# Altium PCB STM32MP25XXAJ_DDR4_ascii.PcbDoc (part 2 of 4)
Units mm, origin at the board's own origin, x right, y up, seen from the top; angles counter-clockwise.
Board outline 172 x 137 mm, 4 copper layers (Top Layer, Signal Layer 1, Signal Layer 2, Bottom Layer), stack 1.614 mm thick; 226 components, 313 nets, 1113 pads, 850 vias.
Unrouted connection lines stored in the file: 13.

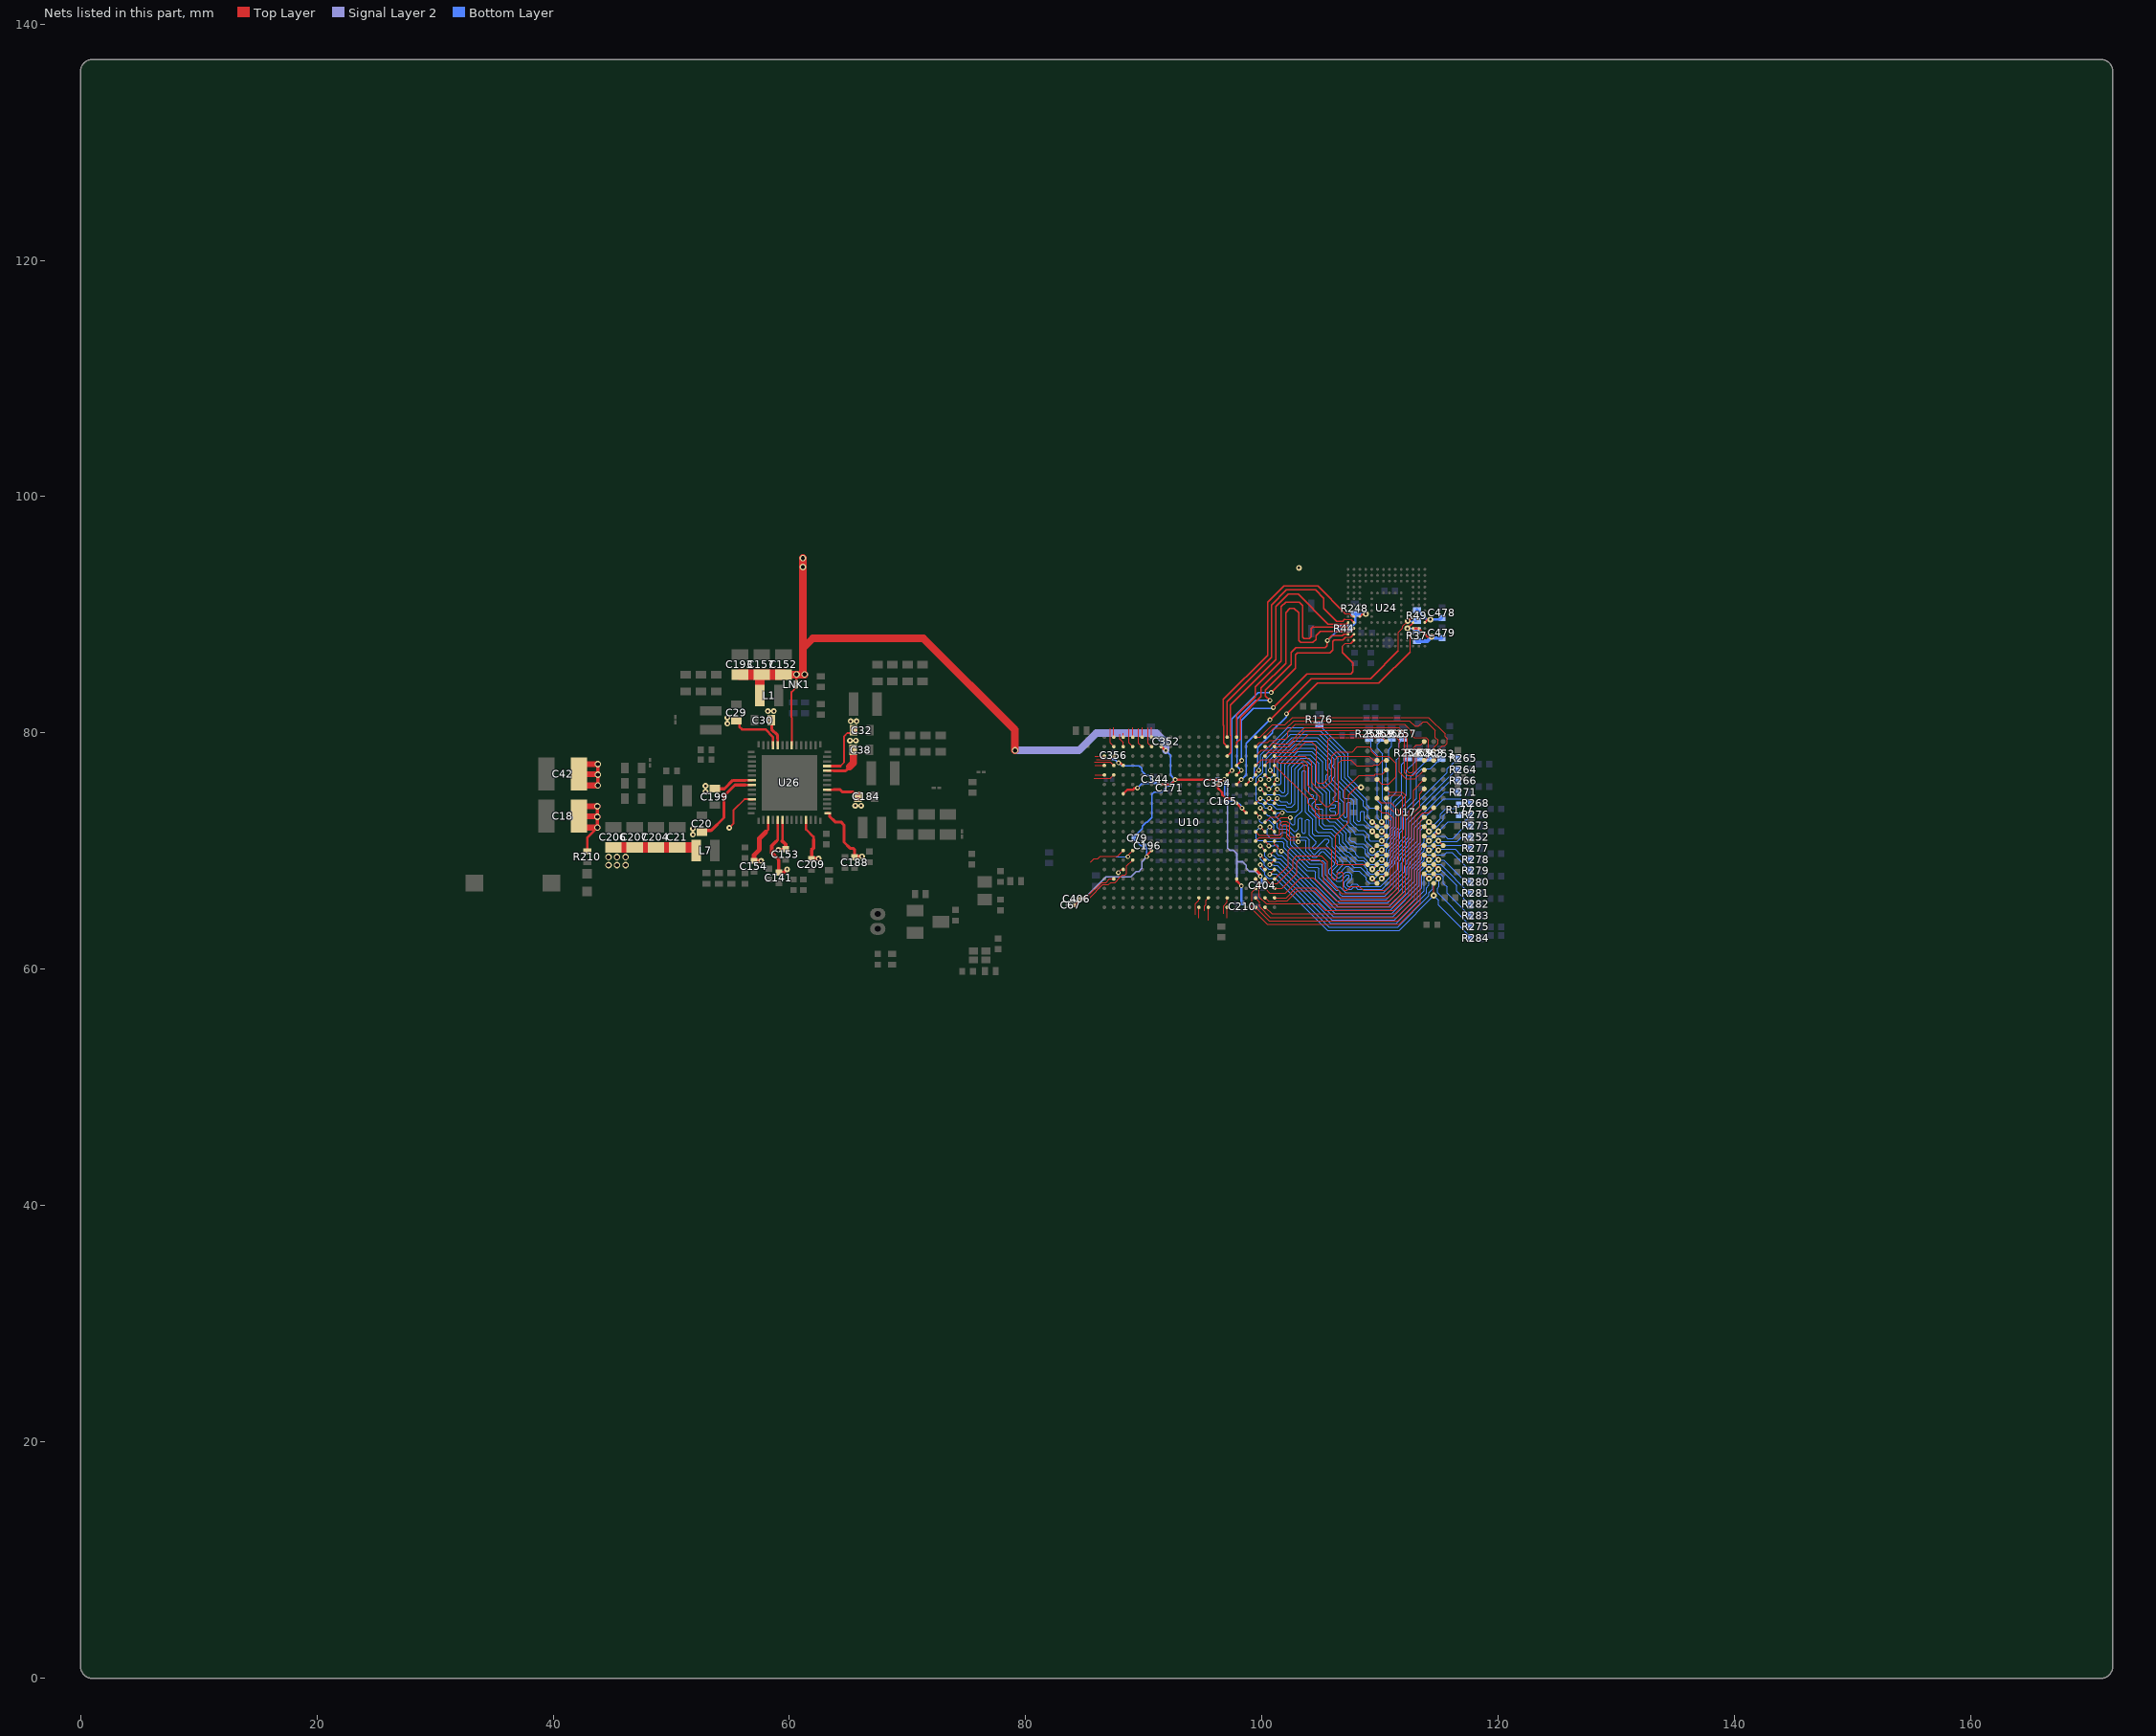
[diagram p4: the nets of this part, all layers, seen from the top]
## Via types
v1: diameter 0.55, hole 0.35, Top Layer to Bottom Layer, 344 vias
v2: diameter 0.5, hole 0.2, Top Layer to Bottom Layer, 250 vias
v3: diameter 0.4, hole 0.2, Top Layer to Bottom Layer, tented both sides, 180 vias
v4: diameter 0.4, hole 0.2, Top Layer to Bottom Layer, 76 vias

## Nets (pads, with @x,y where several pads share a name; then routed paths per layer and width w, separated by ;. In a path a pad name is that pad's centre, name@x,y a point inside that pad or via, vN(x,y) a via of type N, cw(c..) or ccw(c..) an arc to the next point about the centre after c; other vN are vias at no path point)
1V8: C67.2 C79.2 C152.2 C157.2 C165.2 C171.2 C193.2 C196.2 C210.2 C344.2 C352.2 C354.2 C356.2 C404.2 C406.2 C478.2 C479.2 L1.2 LNK1.2 R37.2 R44.2 R49.2 R248.2 U10.B7 U10.D3 U10.F7 U10.F8 U10.F13 U10.G3 U10.H15 U10.J16 U10.N6 U10.R17 U10.T2 U10.T15 U24.C6 U24.M4 U24.N4 U24.P3 U24.P5 | length 130.6
  Top Layer w0.09: v4(84.95,65.985) 84.993,65.985 85.158,66.15 85.228,66.15 86.432,67.355 86.78,67.355 87.075,67.65 U10.T2@87.445,67.65
  Top Layer w0.12: C67.2@84.1,65.4 84.575,65.875 C406.2@84.575,65.975 v4@84.95,65.975 ; v3(90.25,69.525) 90.25,69.65 U10.N6@90.65,70.05
  Top Layer w0.18: U24.C6@108.275,89.85 108.452,90.027 108.727,90.027 v2(108.775,90.075) ; U24.M4@112.775,88.85 U24.N4@113.275,88.85 113.75,88.375 U24.P3@113.775,88.375 ; U24.P3@113.775,88.35 113.975,88.15 v2(114.35,88.15) ; U24.P5@113.775,89.35 114.005,89.58 114.23,89.58 v2(114.25,89.6)
  Top Layer w0.2: LNK1.2@60.6,84.348 v1(60.6,84.95) ; v4(87.85,77.475) 87.888,77.437 88.036,77.437 88.223,77.25 U10.D3@88.25,77.25 ; U10.G3@88.25,74.85 88.612,75.212 89.093,75.212 89.193,75.312 89.412,75.312 v3(89.45,75.35) ; U10.F7@91.45,75.65 92.263,75.65 92.663,76.05 96.526,76.05 96.585,75.99 ; U10.B7@91.45,78.85 91.477,78.85 91.802,78.525 v4(91.85,78.525) ; U10.F13@96.245,75.65 96.585,75.99 ; U10.F13@96.25,75.65 96.25,75.345 96.6,74.995 96.6,74.99 96.638,74.952 96.638,74.749 96.913,74.474 97.426,74.474 U10.J16@98.65,73.25 ; v3(96.8,76.075) 96.762,76.037 96.632,76.037 96.585,75.99 ; U10.T15@97.85,67.65 97.85,67.475 v3(98.25,67.075) ; U10.R17@99.45,68.45 99.812,68.088 99.812,67.913 v3(99.85,67.875)
  Top Layer w0.64: C152.2@59.5,84.95 v1(60.6,84.95) v1(61.28,84.95) 61.142,85.088 61.142,87.175 ; v1(61.142,94.8) 61.142,87.175 ; v1@79.075,78.525 79.075,80.275 71.35,88 61.967,88 61.142,87.175
  Top Layer w0.8: L1.2@57.495,83.175 57.495,84.9 57.545,84.95 C157.2@57.65,84.95
  Top Layer w0.9: C193.2@55.8,84.95 C157.2@57.545,84.95 ; C157.2@57.65,84.95 C152.2@59.5,84.95
  Signal Layer 2 w0.12: v4(84.95,65.985) 86.79,67.825 88.891,67.825 89.341,68.275 89.575,68.275 89.8,68.5 89.8,68.506 89.81,68.516 89.81,69.085 v3(90.25,69.525)
  Signal Layer 2 w0.15: v3(96.8,76.075) 96.825,76.1 96.825,75.999 97.075,75.749 97.075,70.267 97.267,70.075 97.555,70.075 97.875,69.755 97.875,69.425 ; 97.875,69.452 97.875,69.097 ; v3@98.248,67.075 97.875,67.448 97.875,69.097 ; v3(99.85,67.875) 99.425,68.3 98.895,68.3 98.65,68.545 98.65,68.805 98.358,69.097 97.875,69.097
  Signal Layer 2 w0.64: v1@60.6,84.955 v1@61.28,84.955 ; v1(79.1,78.525) 84.507,78.525 85.97,79.988 91.047,79.988 91.85,79.185 v4(91.85,78.525)
  Bottom Layer w0.12: C356.2@87.45,77.85 87.8,77.5 v4@87.825,77.5 ; v4(87.85,77.475) 88.125,77.2 89.258,77.2 89.268,77.21 89.599,77.21 89.81,76.999 89.81,76.781 90.141,76.45 90.384,76.45 ; C79.2@89.15,71.125 89.29,70.985 89.29,70.892 89.566,70.616 89.599,70.616 89.74,70.475 90,70.475 90.226,70.249 90.226,69.549 v3(90.25,69.525) ; C79.2@89.15,71.175 89.29,71.315 89.29,71.365 89.856,71.931 89.856,72.116 90.176,72.435 90.269,72.435 90.69,72.856 90.69,74.815 90.865,74.99 91.508,74.99 92.028,75.51 92.06,75.51 92.175,75.625 v3@92.6,76.05 ; v3(89.45,75.35) 89.815,75.715 90.399,75.715 90.434,75.75 90.615,75.75 90.61,75.755 ; 90.4,76.45 90.384,76.45 ; C344.2@90.975,75.825 90.905,75.755 90.61,75.755 ; C344.2@91,75.739 92.061,75.739 C171.2@92.159,75.641 ; v4@91.825,78.55 91.9,78.625 C352.2@91.9,79 ; v4(91.85,78.525) 92.25,78.125 92.25,76.45 92.6,76.1 v3@92.6,76.05 ; v3(92.65,76.05) v3@92.6,76.05 ; v3@92.65,76.1 v3@92.7,76.1 ; v3@92.671,76.012 v3@92.71,76.05 ; C354.2@96.224,76.051 96.25,76.075 v3(96.8,76.075) 96.84,76.036 96.84,74.43 96.95,74.32 96.95,74.3 97.025,74.225 97.216,74.225 97.726,74.23 97.811,74.23 98.2,73.841 98.2,73.804 98.262,73.742 98.262,73.662 v3@98.25,73.65 ; 90.384,76.45 90.61,76.224 90.61,75.755
  Bottom Layer w0.15: v3(99.85,67.875) 99.95,67.775 C404.2@99.95,67.375
  Bottom Layer w0.2: v3@98.26,67.143 98.266,67.137 C210.2@98.266,65.523 ; R44.2@107.45,88.825 R44.2@107.425,88.85 107.9,89.325 R248.2@107.9,90.075 ; R248.2@107.85,90.075 R248.2@107.9,90.075 ; R248.2@107.9,90.1 R248.2@107.9,90.075 ; v2@108.8,90.075 v2(108.775,90.075) R248.2@107.9,90.075 ; R49.2@113.1,90.45 113.95,89.6 v2(114.25,89.6) 115.075,89.6 C478.2@115.2,89.725
  Bottom Layer w0.3: R37.2@113.125,87.775 113.975,87.775 v2(114.35,88.15) 114.418,88.15 114.543,88.025 C479.2@115.225,88.025
  other v1: 61.131,94.047
  other v2: 103.125,93.975
  other v3: 98.3,73.65
1V8_FB: LNK1.1 U26.35 | length 5.1
  Top Layer w0.15: U26.35@60.2,78.97 60.2,81.311 60.175,81.336 60.175,83.473 LNK1.1@60.6,83.898
3V3: C21.2 C154.2 C204.2 C206.2 C207.2 L7.2 U26.3 U26.53 | length 15.3
  Top Layer w0.15: v2(54.91,71.977) 55.262,72.329 55.262,73.465 56.197,74.4 U26.53@56.83,74.4 ; U26.53@56.62,74.369 56.919,74.369 U26.53@56.95,74.4
  Top Layer w0.21: 57.973,71.598 58.2,71.825 U26.3@58.2,72.63
  Top Layer w0.3: C154.2@56.975,69.175 C154.2@57,69.175 v2@57.585,69.175
  Top Layer w0.4: C154.2@57,69.175 57.014,69.189 57.014,69.685 57.46,70.131 57.46,71.085 57.973,71.598
  Top Layer w0.9: C206.2@45.087,70.323 C21.2@50.5,70.323 51.862,70.323 L7.2@51.887,70.298
  other v1: 44.687,68.823 45.412,68.823 46.137,68.823 44.687,69.498 45.412,69.498 46.137,69.498
  other v2: 57.61,69.175
5V_STLK: C18.1 C20.2 C29.2 C30.2 C32.2 C38.2 C42.1 C153.2 C184.2 C188.2 C199.2 C209.2 R210.1 U26.6 U26.11 U26.15 U26.20 U26.24 U26.25 U26.38 U26.39 U26.49 U26.50 | length 56.5
  Top Layer w0.15: 64.3,77.2 64.625,77.525 64.625,79.731 64.888,79.994 65.319,79.994 C32.2@65.425,80.1
  Top Layer w0.2: R210.1@42.887,69.97 42.887,71.138 v1(43.751,72.002)
  Top Layer w0.21: C29.2@55.525,81.05 55.762,80.813 55.762,80.513 55.975,80.3 57.964,80.3 58.6,79.664 U26.39@58.6,78.97 ; 56.275,75.6 U26.50@56.83,75.6 ; 56.275,76 U26.49@56.83,76 ; U26.38@59,78.97 59,79.525 ; 59.4,70.85 U26.6@59.4,72.63 ; U26.11@61.4,72.63 61.4,71.843 62.04,71.203 62.04,70.975 ; U26.15@63.17,73.2 U26.15@63.245,73.2 U26.15@63.285,73.2 ; U26.20@63.17,75.2 63.725,75.2 ; U26.24@63.17,76.8 63.725,76.8 ; U26.25@63.17,77.2 64.3,77.2
  Top Layer w0.25: C20.2@52.6,71.75 53.375,71.75 54.45,72.825 54.45,74.669 55.381,75.6 56.275,75.6 ; C199.2@53.675,75.275 54.491,75.275 55.216,76 56.275,76 ; C30.2@58.425,81.075 58.494,81.006 58.494,80.308 59,79.802 59,79.525 ; 63.395,73.095 63.395,72.947 63.871,72.472 64.353,72.472 64.625,72.2 64.625,70.759 65.134,70.25 65.379,70.25 65.525,70.104 C188.2@65.525,69.55 ; 63.725,75.2 64.288,75.2 64.463,75.025 65.347,75.025 65.472,74.9 65.55,74.9 65.747,74.703 C184.2@65.747,74.625 ; 63.725,76.8 64.75,76.8 65.075,77.125
  Top Layer w0.3: v1(43.751,72.002) v1(43.751,72.902) v1(43.751,73.802) ; v1(43.776,75.565) v1(43.776,76.465) v1(43.776,77.365) ; v2(59.065,70.11) 59.675,70.11 59.674,70.111 59.674,70.576 59.4,70.85 ; C209.2@61.85,69.38 C209.2@61.875,69.38 ; 62.04,70.975 62.04,70.269 61.875,70.104 C209.2@61.875,69.38 ; v2(62.46,69.38) C209.2@61.875,69.38 ; C188.2@65.525,69.55 v2(66.135,69.55)
  Top Layer w0.5: C18.1@42.187,72.049 42.235,72.002 v1(43.751,72.002) ; C18.1@42.187,72.961 43.679,72.961 43.737,72.902 v1(43.751,72.902) ; C42.1@42.187,75.612 42.235,75.565 v1(43.776,75.565) ; C42.1@42.187,76.523 43.704,76.523 43.762,76.465 v1(43.776,76.465) ; C18.1@42.246,73.802 v1(43.751,73.802) ; C42.1@42.246,77.365 v1(43.776,77.365)
  Top Layer w0.6: 65.075,77.125 65.4,77.45 C38.2@65.4,78.175
  other v2: 51.825,71.4 51.825,71.9 65.575,73.85 66.075,73.85 52.9,75.025 52.9,75.525 65.125,79.35 65.625,79.35 54.75,80.8 65.175,81 65.675,81 54.75,81.3 58.175,81.85 58.675,81.85
5V_VCONN: C141.1 U26.5 | length 5.7
  Top Layer w0.21: 58.877,70.828 59,70.95 U26.5@59,72.63
  Top Layer w0.3: 58.877,70.828 58.51,70.46 58.51,69.865 59.1,69.275 C141.1@59.1,68.2 59.539,68.2 v2(59.8,68.46)
ANA0: U10.V14 | length 1.4
  Top Layer w0.1: 96.75,64.727 96.75,65.374 97.05,65.674 U10.V14@97.05,66.05
ANA1: U10.W14 | length 0.9
  Top Layer w0.1: 97.05,64.356 U10.W14@97.05,65.25
BOOT0: U10.N3 | length 3.2
  Top Layer w0.1: 85.474,69.068 85.784,69.378 86.12,69.378 86.292,69.55 87.233,69.55 87.253,69.57 87.77,69.57 U10.N3@88.25,70.05
BOOT1: U10.N4 | length 1.6
  Top Layer w0.1: v3@88.645,69.65 U10.N4@89.045,70.05
  Bottom Layer w0.1: 87.652,69.525 v3(88.645,69.525)
BOOT2: U10.R3 | length 0.5
  Top Layer w0.09: v4(87.825,68.185) 87.825,68.199 88.052,68.425 88.225,68.425 U10.R3@88.25,68.45
BOOT3: U10.P4 | length 5.3
  Top Layer w0.09: 85.434,66.088 86.511,67.165 87.008,67.165 87.194,67.351 87.568,67.351 87.745,67.528 87.745,67.569 88.164,67.988 88.423,67.988 88.551,68.116 88.551,68.751 U10.P4@89.05,69.25
COMBOPHY_RX1N: U10.W12 | length 1.1
  Top Layer w0.09: 95.45,64.15 U10.W12@95.45,65.25
COMBOPHY_RX1P: U10.V12 | length 1.2
  Top Layer w0.09: 95.15,64.945 95.15,65.372 95.236,65.459 95.236,65.841 U10.V12@95.445,66.05
COMBOPHY_TX1N: U10.W11 | length 0.9
  Top Layer w0.09: 94.645,64.356 94.645,65.245 U10.W11@94.65,65.25
COMBOPHY_TX1P: U10.V11 | length 1.5
  Top Layer w0.09: 94.35,64.63 94.35,65.564 94.632,65.845 94.632,66.032 U10.V11@94.65,66.05
CSI_CKN: U10.C2 | length 1.6
  Top Layer w0.09: 85.967,77.75 87.15,77.75 U10.C2@87.45,78.05
CSI_CKP: U10.C1 | length 0.8
  Top Layer w0.09: 85.875,78.05 U10.C1@86.65,78.05
CSI_D0N: U10.E1 | length 0.8
  Top Layer w0.09: 85.875,76.45 U10.E1@86.65,76.45
CSI_D0P: U10.E2 | length 1.8
  Top Layer w0.09: 85.794,76.15 87.15,76.15 U10.E2@87.45,76.45
CSI_D1N: U10.D2 | length 1.7
  Top Layer w0.09: 85.823,77.545 87.16,77.545 U10.D2@87.45,77.255
CSI_D1P: U10.D1 | length 0.8
  Top Layer w0.09: 85.875,77.25 U10.D1@86.65,77.25
DDR_A0: R265.1 U10.H19 U17.P3 | length 32.7
  Top Layer w0.09: U10.H19@101.046,74.05 101.062,74.066 101.062,74.261 101.251,74.45 v3(101.275,74.45) ; v2@110.132,69.268 U17.P3@110.527,68.873
  Bottom Layer w0.09: v3(101.275,74.45) 101.55,74.175 102.087,74.175 102.234,74.028 102.402,74.028 102.506,74.133 102.506,77.111 103.259,77.864 103.977,77.864 104.539,77.301 104.539,75.396 105.148,74.788 105.148,74.12 105.01,73.982 104.624,73.982 104.539,73.896 104.539,73.67 104.634,73.575 105.06,73.575 105.148,73.487 105.148,72.317 105.291,72.174 106.035,72.174 106.821,71.388 106.821,70.729 107.329,70.221 107.548,70.221 107.922,69.847 107.922,69.734 108.179,69.477 108.564,69.477 109.162,68.879 109.551,68.879 109.867,69.195 110.048,69.195 110.127,69.273 110.182,69.273 110.712,69.803 110.712,70.062 111.368,70.718 111.368,70.843 111.634,71.108 111.634,71.545 111.983,71.894 111.983,72.95 115.675,76.642 115.675,76.97 116.25,77.545 116.39,77.545 116.6,77.755 R265.1@116.6,77.848
  other v2: 110.125,69.275
DDR_A1: R281.1 U10.N18 U17.P7 | length 25.2
  Top Layer w0.09: v3(99.85,70.45) U10.N18@100.25,70.05 ; U17.P7@113.727,68.873 v2@114.127,68.473
  Bottom Layer w0.09: v3(99.85,70.45) 100.243,70.057 100.243,69.556 100.554,69.246 100.966,69.246 101.138,69.073 101.413,69.073 106.026,64.46 111.107,64.46 113.522,66.875 113.522,67.946 114.049,68.473 114.127,68.473 114.348,68.473 114.75,68.875 115.125,68.875 117.575,66.425 R281.1@117.65,66.425
  other v2: 114.125,68.475
DDR_A2: R268.1 U10.K18 U17.R3 | length 34.4
  Top Layer w0.09: U10.K18@100.255,72.45 100.712,72.907 101.275,72.907 101.618,73.25 v3(101.7,73.25) v3@101.704,73.25 ; v2(110.125,67.675) 110.522,68.073 U17.R3@110.527,68.073
  Bottom Layer w0.09: v3@101.704,73.25 v3(101.7,73.25) 101.335,73.25 101.157,73.073 101.157,72.933 101.58,72.511 101.58,72.244 101.667,72.156 102.229,72.156 102.711,71.674 102.876,71.674 103.088,71.886 103.088,72.733 103.177,72.822 103.299,72.822 103.401,72.72 103.401,71.579 103.478,71.502 103.594,71.502 103.695,71.603 103.695,72.586 103.785,72.675 103.893,72.675 103.988,72.581 103.988,71.363 104.563,70.788 104.563,70.672 104.278,70.387 104.278,70.253 104.369,70.162 104.496,70.162 105.348,71.014 105.554,71.014 105.661,70.907 105.661,70.778 105.468,70.585 105.468,70.442 106.843,69.066 106.843,68.843 106.331,68.331 106.331,68.2 106.413,68.118 106.537,68.118 107.122,68.703 107.328,68.703 107.705,68.325 108.223,68.325 108.802,67.747 108.802,67.523 109.045,67.28 109.726,67.28 v2@110.119,67.673 ; v2@110.127,67.673 110.182,67.673 110.732,68.223 110.732,68.429 111.255,68.952 111.255,69.158 111.472,69.375 111.472,69.517 112.474,70.519 112.474,70.663 112.883,71.071 112.883,71.946 115.37,74.434 117.336,74.434 117.415,74.355 117.415,74.26 R268.1@117.625,74.05
DDR_A3: R279.1 U10.M18 U17.N7 | length 24.3
  Top Layer w0.09: U10.M18@100.25,70.85 100.575,70.525 v3(100.575,70.45) ; U17.N7@113.727,69.673 v2(114.125,69.275)
  Bottom Layer w0.09: v3(100.575,70.45) 100.994,70.45 101.075,70.531 101.269,70.531 101.375,70.425 101.375,70.25 101.242,70.117 101.242,69.79 101.378,69.653 101.653,69.653 106.267,65.04 110.866,65.04 113.102,67.275 113.102,68.304 114.071,69.273 114.328,69.273 114.731,69.677 115.402,69.677 115.624,69.899 116.047,69.899 117.303,68.644 117.42,68.644 117.63,68.434 R279.1@117.63,68.355
DDR_A4: R263.1 U10.G19 U17.N3 | length 30.9
  Top Layer w0.09: U10.G19@101.05,74.854 101.057,74.861 101.057,75.066 101.242,75.25 v3(101.275,75.25) ; v2@110.127,70.073 110.127,70.069 U17.N3@110.53,69.667
  Bottom Layer w0.09: v3@101.285,75.25 101.392,75.25 101.692,74.95 101.835,74.95 101.926,75.041 101.926,77.351 103.019,78.444 104.217,78.444 105.119,77.541 105.119,75.637 105.728,75.028 105.728,74.034 105.809,73.952 106.142,73.952 106.231,73.863 106.231,73.725 106.154,73.648 105.809,73.648 105.728,73.567 105.728,73.441 105.815,73.354 106.133,73.354 106.23,73.258 106.23,73.13 106.151,73.051 105.819,73.051 105.728,72.96 105.728,72.848 105.822,72.754 106.275,72.754 107.501,71.528 107.501,71.25 107.401,71.15 107.401,70.969 107.561,70.809 107.781,70.809 107.98,70.61 108.592,70.61 108.935,70.267 108.935,69.914 109.174,69.675 109.485,69.675 109.823,70.013 110.062,70.013 v2(110.125,70.075) ; v2@110.159,70.075 110.919,70.836 110.919,71.009 111.254,71.343 111.254,71.702 111.553,72.002 111.553,73.453 112.595,74.495 112.595,76.343 113.892,77.64 114.015,77.64 R263.1@114.225,77.85
DDR_A5: R282.1 U10.P19 U17.P8 | length 24.1
  Top Layer w0.09: v3@100.645,68.85 100.647,68.85 101.047,69.25 U10.P19@101.055,69.25 ; U17.P8@114.527,68.873 v2@114.927,68.473
  Bottom Layer w0.09: v3@100.66,68.85 100.951,68.85 101.018,68.783 101.293,68.783 105.906,64.17 111.227,64.17 ; 111.227,64.17 113.725,66.668 113.725,67.834 113.966,68.075 114.36,68.075 114.758,68.473 v2@114.925,68.473 ; v2(114.925,68.475) 115.004,68.397 115.178,68.397 116.47,67.104 116.47,66.605 R282.1@117.625,65.45
  other v3: 100.65,68.85
DDR_A6: R264.1 U10.H18 U17.P2 | length 32.4
  Top Layer w0.09: U10.H18@100.255,74.05 100.575,74.37 v3(100.575,74.45) ; v2@109.327,68.473 U17.P2@109.727,68.873
  Bottom Layer w0.09: v3(100.575,74.45) 100.618,74.45 100.783,74.285 100.923,74.285 101.323,73.885 101.967,73.885 102.114,73.738 102.522,73.738 102.796,74.013 102.796,76.991 103.379,77.574 103.857,77.574 104.249,77.181 104.249,75.276 104.652,74.874 104.652,74.419 104.249,74.016 104.249,73.55 104.858,72.941 104.858,72.197 105.17,71.884 105.914,71.884 106.531,71.267 106.531,70.609 107.209,69.931 107.333,69.931 108.07,69.193 108.559,69.193 v2@109.303,68.449 ; v2@109.327,68.473 109.442,68.473 109.847,68.878 110.29,68.878 110.585,69.173 110.585,69.407 110.902,69.724 110.902,69.919 111.646,70.664 111.646,70.784 112.198,71.335 112.198,72.656 116.442,76.9 R264.1@116.654,76.9
  other v2: 109.325,68.475
DDR_A7: R275.1 U10.R19 U17.R8 | length 24.6
  Top Layer w0.09: v3(100.65,68.05) U10.R19@101.05,68.45 ; U17.R8@114.527,68.073 v2(114.925,67.675)
  Bottom Layer w0.09: v3(100.65,68.05) 101.196,68.05 105.656,63.59 111.477,63.59 114.13,66.243 ; 114.125,66.248 114.125,66.475 114.45,66.8 114.45,67.201 v2(114.925,67.675) 114.994,67.606 114.994,67.017 114.84,66.863 114.84,66.493 117.42,63.913 117.42,63.815 R275.1@117.63,63.605
DDR_A8: R266.1 U10.H17 U17.R2 | length 33.8
  Top Layer w0.09: U10.H17@99.455,74.05 v3@99.85,74.445 ; U17.R2@109.727,68.073 v2@110.127,68.473
  Bottom Layer w0.09: v3(99.85,74.45) 99.9,74.4 100.125,74.4 100.53,73.995 100.803,73.995 101.086,73.712 ; 101.085,73.71 101.199,73.595 101.847,73.595 102.095,73.347 102.882,73.347 103.086,73.551 103.086,76.871 103.499,77.284 103.736,77.284 103.959,77.061 103.959,74.909 104.062,74.805 104.25,74.805 104.362,74.693 104.362,74.547 104.263,74.449 104.053,74.449 ; 104.052,74.449 103.959,74.356 103.959,73.429 104.568,72.821 104.568,71.752 104.725,71.594 105.794,71.594 106.241,71.147 106.241,70.489 107.089,69.641 107.213,69.641 107.948,68.905 108.48,68.905 108.914,68.471 108.914,68.321 109.158,68.077 109.493,68.077 109.826,68.41 110.119,68.41 110.794,69.085 110.794,69.291 111.092,69.589 111.092,69.802 111.908,70.618 111.908,70.709 112.434,71.235 112.434,72.438 115.947,75.95 R266.1@116.6,75.95
  other v2: 110.125,68.475
DDR_A9: R283.1 U10.P18 U17.R7 | length 26
  Top Layer w0.09: v3(99.85,69.65) U10.P18@100.25,69.25 ; U17.R7@113.727,68.073 v2@114.127,67.673
  Bottom Layer w0.09: v3(99.85,69.65) 99.85,69.338 100.195,68.993 100.195,68.81 100.543,68.463 101.204,68.463 105.786,63.88 111.355,63.88 113.925,66.448 113.925,66.914 114.129,67.118 v2@114.129,67.671 ; v2(114.125,67.675) 114.366,67.675 114.761,68.07 115.088,68.07 115.35,67.808 115.35,67.275 115.659,66.966 115.659,66.466 117.293,64.832 117.42,64.832 117.6,64.652 R283.1@117.6,64.525
DDR_A10: R254.1 U10.F19 U17.M3 | length 28.6
  Top Layer w0.09: U10.F19@101.046,75.654 101.046,75.88 101.208,76.042 101.208,76.05 v3(101.275,76.05) ; v2@110.127,70.872 U17.M3@110.526,70.473
  Bottom Layer w0.09: v3@101.285,76.05 101.325,76.09 101.325,77.57 102.779,79.024 104.457,79.024 105.813,77.668 105.813,77.505 105.699,77.391 105.699,77.005 105.85,76.854 105.85,76.449 105.699,76.298 105.699,75.877 106.572,75.004 106.572,74.445 106.902,74.115 ; 106.9,74.115 106.9,72.949 106.986,72.863 107.109,72.863 107.192,72.946 ; 107.19,72.946 107.19,74.067 ; 107.192,74.067 107.275,74.15 107.4,74.15 107.48,74.07 107.48,72.369 108.112,71.737 108.607,71.737 109.055,71.289 109.055,70.967 109.149,70.873 110.187,70.873 110.84,71.526 110.84,71.826 111.142,72.128 111.142,74.127 111.815,74.801 111.815,77.34 R254.1@112.325,77.85
  other v2: 110.125,70.875
DDR_A11: R271.1 U10.K19 U17.T2 | length 31.9
  Top Layer w0.09: U10.K19@101.055,72.45 101.079,72.474 101.259,72.474 101.623,72.838 v3@102.388,72.838 ; v2@109.348,67.663 109.727,67.284 U17.T2@109.727,67.273
  Bottom Layer w0.09: v3(102.39,72.84) 102.39,72.405 102.561,72.234 102.705,72.234 102.798,72.327 102.798,72.853 103.376,73.431 103.376,76.75 103.459,76.833 103.59,76.833 103.669,76.754 103.669,73.309 104.278,72.701 104.278,71.484 104.457,71.304 105.674,71.304 105.951,71.027 105.951,70.368 106.969,69.351 107.09,69.351 107.826,68.614 ; 107.827,68.615 108.343,68.615 v2@109.302,67.657 ; v2@109.327,67.673 109.508,67.673 109.911,68.076 110.288,68.076 110.522,68.31 110.522,68.516 111.018,69.012 111.018,69.218 111.282,69.482 111.282,69.666 112.212,70.596 112.212,70.734 112.66,71.183 112.66,72.195 115.465,75 R271.1@116.6,75
  other v2: 109.325,67.675
DDR_A12: R277.1 U10.L18 U17.M7 | length 25.9
  Top Layer w0.09: v3(99.845,72.05) 99.85,72.05 U10.L18@100.25,71.65 ; U17.M7@113.725,70.475 v2(114.125,70.075)
  Bottom Layer w0.09: v3(99.845,72.05) 99.517,71.722 99.517,71.056 99.67,70.902 100.223,70.902 100.304,70.821 101.68,70.821 101.843,70.658 101.843,70.284 103.792,68.335 104.404,68.335 104.513,68.225 104.513,67.613 106.507,65.62 110.626,65.62 112.682,67.676 112.682,68.478 113.522,69.318 113.522,69.535 114.06,70.073 v2(114.125,70.075) 114.307,70.073 114.713,70.479 117.42,70.479 117.63,70.269 R277.1@117.63,70.255
DDR_A13: R284.1 U10.R18 U17.T8 | length 25
  Top Layer w0.09: v3(99.85,68.85) U10.R18@100.25,68.45 ; v2@114.527,66.248 U17.T8@114.527,67.273
  Bottom Layer w0.09: v3@99.86,68.85 99.86,68.567 100.236,68.191 100.236,67.97 100.505,67.702 101.134,67.702 105.536,63.3 111.597,63.3 114.525,66.228 v2@114.525,66.25 ; v2@114.525,66.275 v2@114.525,66.25 ; R284.1@117.65,62.625 117.65,62.717 114.917,65.449 114.917,65.857 v2@114.525,66.25
  other v2: 114.525,66.25
DDR_ACTN: R256.1 U10.E19 U17.L3 | length 27.5
  Top Layer w0.09: v3@100.68,76.85 100.68,76.82 U10.E19@101.05,76.45 ; v2@110.127,71.673 U17.L3@110.527,71.273
  Bottom Layer w0.09: v3(100.69,76.85) 100.699,76.859 100.699,77.764 102.538,79.604 104.697,79.604 106.43,77.871 106.43,75.966 108.06,74.336 108.06,72.613 108.14,72.532 108.266,72.532 108.35,72.616 108.35,73.309 108.422,73.382 108.564,73.382 108.64,73.306 108.64,72.6 ; 108.642,72.6 109.163,72.078 109.536,72.078 109.728,71.887 109.851,71.887 110.064,71.673 v2@110.127,71.673 ; v2(110.125,71.675) 110.152,71.675 110.726,72.249 110.726,75.326 110.625,75.427 110.625,77 110.53,77.095 110.53,77.516 110.71,77.697 110.71,78.61 110.975,78.875 R256.1@110.975,79.475
DDR_BA0: R253.1 U10.G18 U17.N2 | length 32.1
  Top Layer w0.09: v3@99.85,75.268 v3(99.85,75.265) 99.85,75.258 U10.G18@100.25,74.858 ; v2@109.329,69.271 109.727,69.668 U17.N2@109.727,69.673
  Bottom Layer w0.09: v3(99.85,75.265) 100.313,74.802 101.43,74.802 101.572,74.66 101.956,74.66 102.216,74.921 102.216,77.231 103.139,78.154 104.097,78.154 104.829,77.421 104.829,75.517 105.438,74.908 105.438,72.728 105.702,72.464 106.155,72.464 107.111,71.508 107.111,70.849 107.449,70.511 107.669,70.511 107.788,70.392 108.463,70.392 108.74,70.114 108.74,69.758 109.225,69.273 109.422,69.273 109.827,69.678 110.29,69.678 110.522,69.91 110.522,70.17 111.178,70.826 111.178,70.999 111.444,71.265 111.444,71.623 111.77,71.95 111.77,73.16 113.07,74.46 113.07,76.53 113.504,76.964 114.242,76.964 114.869,77.59 114.965,77.59 R253.1@115.175,77.8
  other v2: 109.325,69.275
DDR_BA1: R280.1 U10.N19 U17.N8 | length 23.5
  Top Layer w0.09: v3(100.65,69.65) U10.N19@101.05,70.05 ; U17.N8@114.527,69.673 v2(114.925,69.275) v2@114.897,69.273
  Bottom Layer w0.09: v3(100.65,69.65) 100.661,69.639 100.982,69.639 101.258,69.363 101.533,69.363 106.146,64.75 110.986,64.75 113.332,67.095 113.332,68.244 113.964,68.876 114.34,68.876 114.738,69.273 v2(114.925,69.275) ; v2(114.925,69.275) 114.958,69.242 115.392,69.242 117.234,67.4 R280.1@117.65,67.4
DDR_BG0: R255.1 U10.F18 U17.M2 | length 28.8
  Top Layer w0.09: U10.F18@100.25,75.65 100.25,75.598 100.575,75.273 v3(100.575,75.25) ; v2@109.335,70.081 109.335,70.093 109.715,70.473 U17.M2@109.727,70.473
  Bottom Layer w0.09: v3@100.585,75.25 100.995,75.66 101.546,75.66 101.63,75.744 101.63,77.465 102.899,78.734 104.337,78.734 105.409,77.662 105.409,76.885 105.56,76.734 105.56,76.569 105.409,76.418 105.409,75.757 106.282,74.884 106.282,74.751 106.018,74.487 106.018,74.359 106.135,74.242 106.365,74.242 106.575,74.032 106.575,72.864 106.866,72.573 107.117,72.573 107.19,72.5 107.19,72.249 107.791,71.648 107.791,71.525 107.906,71.41 108.35,71.41 ; 108.35,71.415 108.518,71.415 108.75,71.183 108.75,70.861 109.327,70.285 109.327,70.081 109.724,70.478 110.293,70.478 110.571,70.757 110.571,70.93 111.064,71.422 111.064,71.781 111.346,72.063 111.346,73.871 112.221,74.746 112.221,76.854 112.97,77.604 112.97,77.64 113.18,77.85 R255.1@113.275,77.85
  other v2: 109.33,70.083
DDR_BG1: R252.1 U10.L19 U17.M9 | length 24.9
  Top Layer w0.09: v3@100.65,72.05 U10.L19@101.05,71.65 ; v2(114.925,70.875) U17.M9@115.327,70.473
  Top Layer w0.2: v3(100.645,72.05) v3@100.65,72.05
  Bottom Layer w0.09: v3(100.645,72.05) 100.428,71.834 100.428,71.377 100.695,71.111 101.8,71.111 102.133,70.778 102.133,70.404 103.743,68.793 103.912,68.625 104.705,68.625 104.803,68.526 104.803,67.734 105.043,67.493 106.627,65.91 110.506,65.91 112.472,67.876 112.472,68.565 113.312,69.405 113.312,69.654 113.704,70.047 113.704,70.216 113.96,70.471 114.295,70.471 114.697,70.873 v2(114.925,70.875) ; v2(114.925,70.875) 114.966,70.833 116.511,70.833 116.876,71.199 R252.1@117.625,71.2
DDR_CASN: R278.1 U10.M19 U17.M8 | length 22.6
  Top Layer w0.09: U10.M19@101.05,70.85 101.05,70.575 v3@101.625,70 ; U17.M8@114.527,70.473 v2(114.925,70.075) v2(114.925,70.075)
  Bottom Layer w0.09: v3@101.63,69.999 101.717,69.999 106.387,65.33 110.746,65.33 112.892,67.475 112.892,68.391 113.73,69.229 113.73,69.439 113.971,69.68 114.438,69.68 114.831,70.073 v2(114.925,70.075) ; v2(114.925,70.075) 115.036,70.075 115.149,70.189 116.332,70.189 116.775,69.746 ; 116.775,69.75 117.225,69.3 R278.1@117.625,69.3
  other v3: 101.63,70
DDR_CKE: R259.1 U10.F17 U17.K2 | length 26.8
  Top Layer w0.09: U10.F17@99.45,75.65 99.87,76.07 v3(99.88,76.07) ; v2@109.333,72.463 109.723,72.073 U17.K2@109.727,72.073
  Bottom Layer w0.09: v3(99.88,76.07) 100.345,76.535 100.345,77.82 102.418,79.894 104.817,79.894 106.72,77.991 106.72,76.086 108.568,74.238 108.568,73.813 108.93,73.451 108.93,72.87 v2(109.325,72.475) 109.408,72.475 109.806,72.077 110.285,72.077 110.52,72.312 110.52,74.025 110.2,74.345 110.2,78.242 109.73,78.712 109.73,79.039 110.025,79.334 R259.1@110.025,79.5
DDR_CLK_N: R177.2 U10.L17 U17.K8 | length 30
  Top Layer w0.09: U10.L17@99.447,71.652 99.744,71.355 101.393,71.355 101.484,71.446 ; 101.485,71.448 101.485,72.289 101.721,72.525 102.116,72.525 102.338,72.303 102.338,71.273 102.426,71.186 102.85,71.186 102.978,71.314 v4(103.058,71.314) ; v2(114.125,72.475) U17.K8@114.527,72.073
  Bottom Layer w0.09: v4(103.058,71.314) 103.134,71.314 103.266,71.183 103.758,71.183 103.987,70.954 103.987,70.134 104.376,69.745 104.488,69.745 104.956,70.212 105.288,70.212 106.38,69.12 106.38,68.789 105.923,68.333 105.923,68.197 106.396,67.725 106.554,67.725 107.069,68.24 107.38,68.24 107.46,68.16 107.621,67.999 107.621,67.672 107.216,67.266 107.216,67.113 107.299,67.03 107.476,67.03 107.656,67.21 108.028,67.21 108.208,67.03 110.042,67.03 111.505,68.493 111.505,69.055 111.722,69.271 111.722,69.413 ; 111.725,69.425 113.151,70.851 113.151,71.847 113.493,72.189 113.836,72.189 v2@114.122,72.475 ; v2(114.125,72.475) 114.166,72.475 114.38,72.261 114.614,72.261 115.1,72.747 115.1,73.115 115.584,73.599 116.348,73.599 116.47,73.721 116.47,73.74 116.68,73.95 R177.2@116.775,73.95
DDR_CLK_P: R177.1 U10.M17 U17.K7 | length 30
  Top Layer w0.09: U10.M17@99.45,70.85 99.745,71.145 101.536,71.145 101.735,71.344 ; U10.M17@99.455,70.85 U10.M17@99.457,70.853 ; 101.735,71.344 101.735,72.186 101.825,72.275 102.013,72.275 102.088,72.2 102.088,71.17 102.322,70.936 102.85,70.936 102.999,70.787 v4(103.058,70.787) ; U17.K7@113.727,72.073 v2(114.125,71.675)
  Bottom Layer w0.09: v4(103.058,70.787) 103.12,70.787 103.266,70.933 103.655,70.933 103.737,70.851 103.737,70.031 104.273,69.495 104.592,69.495 105.059,69.962 105.184,69.962 106.13,69.016 106.13,68.893 105.673,68.436 105.673,68.094 106.292,67.475 106.658,67.475 107.173,67.99 107.277,67.99 107.371,67.895 107.371,67.776 106.966,67.37 106.966,67.01 107.195,66.78 107.58,66.78 107.76,66.96 107.925,66.96 108.104,66.78 110.146,66.78 111.755,68.389 111.755,68.951 111.972,69.168 111.972,69.319 ; 111.975,69.322 113.401,70.747 113.401,71.743 113.596,71.939 113.859,71.939 v2@114.123,71.675 ; v2(114.125,71.675) 114.134,71.675 114.47,72.011 114.716,72.011 cw(c114.925,71.675) 114.72,72.013 115.35,72.643 115.35,73.011 115.687,73.349 116.367,73.349 116.455,73.26 116.565,73.26 R177.1@116.775,73.05
DDR_CSN: R273.1 U10.J17 U17.L7 | length 26.9
  Top Layer w0.09: U10.J17@99.45,73.25 99.8,72.9 v3(99.8,72.85) ; U17.L7@113.727,71.273 v2(114.125,70.875)
  Bottom Layer w0.09: v3@99.806,72.844 99.806,72.526 99.931,72.402 100.094,72.402 100.327,72.634 100.565,72.634 101,72.2 101,71.494 101.093,71.401 101.525,71.401 101.7,71.576 101.989,71.576 102.423,71.142 102.423,70.524 104.032,68.915 105.003,68.915 105.093,68.824 105.093,67.854 106.25,66.697 106.458,66.697 106.601,66.554 106.601,66.346 106.747,66.2 110.386,66.2 112.262,68.076 112.262,68.652 112.55,68.94 112.55,69.085 113.102,69.636 113.102,69.747 113.509,70.155 113.509,70.303 114.082,70.875 v2(114.125,70.875) ; v2@114.099,70.873 114.154,70.873 114.554,71.273 115.518,71.273 115.711,71.08 116.129,71.08 117.157,72.109 117.584,72.109 R273.1@117.63,72.155
DDR_DQ0: U10.W18 U17.F7 | length 22.8
  Top Layer w0.09: U10.W18@100.26,65.25 100.822,64.688 111.248,64.688 112.66,66.1 112.66,73.118 113.34,73.798 113.34,74.89 U17.F7@113.725,75.275
DDR_DQ1: U10.W17 U17.H8 | length 23.6
  Top Layer w0.09: U10.W17@99.45,65.25 99.45,65.237 100.579,64.108 111.489,64.108 113.14,65.759 113.14,72.778 113.603,73.242 114.09,73.242 ; 114.096,73.242 U17.H8@114.527,73.673
DDR_DQ2: U10.V17 U17.H7 | length 23.2
  Top Layer w0.09: U10.V17@99.45,66.05 99.45,66.018 99.78,65.688 99.78,65.317 100.699,64.398 111.368,64.398 112.9,65.929 112.9,72.948 113.627,73.675 U17.H7@113.725,73.675 ; U17.H7@113.725,73.673 U17.H7@113.727,73.673
DDR_DQ3: U10.U17 U17.J7 | length 24.8
  Top Layer w0.09: U10.U17@99.455,66.85 99.15,66.545 99.15,65.111 100.443,63.818 111.609,63.818 113.38,65.589 113.38,72.53 U17.J7@113.725,72.875
DDR_DQ4: U10.T19 U17.J3 | length 22.4
  Top Layer w0.09: U10.T19@101.059,67.645 101.101,67.645 102.209,68.753 102.209,70.061 102.441,70.294 105.635,70.294 105.884,70.045 105.884,67.756 106.061,67.58 106.209,67.58 106.343,67.714 106.343,68.063 106.505,68.224 106.74,68.224 106.857,68.107 106.857,66.783 106.962,66.678 107.182,66.678 107.532,67.028 108.222,67.028 108.572,66.678 110.416,66.678 110.87,67.132 110.87,72.513 110.527,72.856 U17.J3@110.527,72.873
DDR_DQ5: U10.T18 U17.H2 | length 22.4
  Top Layer w0.09: U10.T18@100.255,67.65 100.628,67.277 101.302,67.277 102.604,68.579 102.604,69.281 102.917,69.594 105.005,69.594 105.533,69.065 105.533,67.626 106.771,66.388 110.536,66.388 111.11,66.962 111.11,72.778 110.635,73.253 110.147,73.253 U17.H2@109.727,73.673
DDR_DQ6: U10.U19 U17.H3 | length 21.7
  Top Layer w0.09: U10.U19@101.06,66.85 101.707,66.85 102.952,68.095 102.952,69.095 103.144,69.287 104.852,69.287 105.209,68.929 105.209,67.448 106.559,66.098 110.656,66.098 111.35,66.792 111.35,73.125 110.852,73.623 110.577,73.623 U17.H3@110.527,73.673
DDR_DQ7: U10.U18 U17.G2 | length 22.3
  Top Layer w0.09: U10.U18@100.255,66.85 100.655,66.45 101.979,66.45 103.279,67.75 104.344,67.75 106.286,65.808 110.78,65.808 111.59,66.618 ; U17.G2@109.73,74.467 110.08,74.117 110.877,74.117 111.592,73.402 111.592,66.62
DDR_DQ8: U10.C17 U17.D7 | length 18.5
  Top Layer w0.09: U10.C17@99.455,78.05 99.955,78.55 102.555,78.55 103.913,79.908 103.916,79.908 ; 103.916,79.91 111.064,79.91 111.61,79.364 111.61,76.689 112.18,76.118 112.968,76.118 U17.D7@113.725,76.875
DDR_DQ9: U10.A18 U17.B8 | length 17.6
  Top Layer w0.09: U10.A18@100.25,79.65 100.25,79.66 100.997,80.407 102.073,80.407 102.696,81.03 112.48,81.03 112.935,80.575 113.245,80.575 113.631,80.962 113.937,80.962 114.665,80.234 114.665,79.623 114.88,79.408 114.88,79.113 114.534,78.767 114.534,78.485 U17.B8@114.525,78.475
DDR_DQ10: U10.B17 U17.C7 | length 18.3
  Top Layer w0.09: U10.B17@99.45,78.85 99.803,79.203 100.471,79.203 100.623,79.355 101.196,79.355 101.341,79.5 102,79.5 102.175,79.675 102.175,80.077 102.838,80.74 112.043,80.74 112.65,80.133 112.65,79.829 112.858,79.62 113.868,79.62 114.075,79.413 114.075,78.026 U17.C7@113.725,77.675
DDR_DQ11: U10.A17 U17.C8 | length 20.2
  Top Layer w0.09: U10.A17@99.45,79.65 99.824,79.65 100.871,80.697 101.953,80.697 102.576,81.32 114.085,81.32 115.482,79.923 115.482,79.708 115.68,79.51 115.68,79.128 115.455,78.903 115.25,78.903 114.929,78.582 114.929,78.079 U17.C8@114.525,77.675
DDR_DQ12: U10.D19 U17.D3 | length 14.6
  Top Layer w0.09: U10.D19@101.057,77.257 103.862,74.452 103.862,74.05 104.517,73.395 104.517,73.068 104.811,72.775 106.463,72.775 106.994,73.306 106.994,75.222 108.193,76.42 109.495,76.42 109.598,76.523 110.186,76.523 U17.D3@110.53,76.867
DDR_DQ13: U10.D18 U17.C3 | length 18.7
  Top Layer w0.09: U10.D18@100.252,77.248 100.57,77.565 101.325,77.565 101.445,77.445 103.385,77.445 103.602,77.227 103.602,75.266 104.545,74.323 104.545,73.92 104.807,73.658 104.807,73.189 104.931,73.065 106.318,73.065 106.467,73.214 106.467,77.449 106.735,77.717 107.508,77.717 108,77.225 ; 108,77.221 109.379,77.221 109.465,77.306 109.865,77.306 110.212,77.653 110.516,77.653 U17.C3@110.53,77.667
DDR_DQ14: U10.D17 U17.C2 | length 17.3
  Top Layer w0.09: U10.D17@99.452,77.248 99.96,77.755 103.485,77.755 ; 103.485,77.755 103.892,77.347 103.892,75.575 104.892,74.575 104.892,74.253 105.37,73.775 105.65,73.775 106.177,74.302 106.177,77.761 106.444,78.028 108.775,78.028 108.778,78.03 109.072,78.03 109.413,77.689 109.711,77.689 U17.C2@109.725,77.675
DDR_DQ15: U10.C18 U17.A3 | length 17.6
  Top Layer w0.09: U10.C18@100.252,78.048 100.555,78.35 102.765,78.35 103.665,79.25 104.2,79.25 104.592,78.858 104.592,75.903 104.747,75.748 105.233,75.748 105.597,76.111 105.597,79.425 105.792,79.62 110.18,79.62 U17.A3@110.525,79.275
DDR_DQM0: U10.T17 U17.E7 | length 25.7
  Top Layer w0.09: U10.T17@99.455,67.65 99.755,67.35 99.755,66.128 100.338,65.545 104.775,65.545 105.342,64.978 111.124,64.978 112.42,66.274 112.42,73.395 112.812,73.787 112.812,75.163 U17.E7@113.725,76.075
DDR_DQM1: U10.C19 U17.E2 | length 18.8
  Top Layer w0.09: U10.C19@101.05,78.05 103.616,78.05 104.182,77.484 104.182,75.818 104.621,75.379 105.328,75.379 105.887,75.938 105.887,78.029 106.258,78.4 107.625,78.4 108.055,78.83 109.072,78.83 109.28,78.622 109.28,78.432 109.306,78.406 109.675,78.037 110.721,78.037 111.32,77.439 111.32,76.287 110.707,75.675 110.132,75.675 U17.E2@109.734,76.073
DDR_DQS0_N: U10.V18 U17.F3 | length 23.6
  Top Layer w0.09: U10.V18@100.255,66.05 100.554,65.751 101.164,65.751 101.218,65.805 102.148,65.805 102.986,66.643 104.418,66.643 105.792,65.268 111.004,65.268 112.13,66.395 112.13,74.733 111.873,74.99 110.806,74.99 U17.F3@110.53,75.267
DDR_DQS0_P: U10.V19 U17.G3 | length 21.8
  Top Layer w0.09: U10.V19@101.05,66.05 102.039,66.05 102.883,66.893 104.521,66.893 105.896,65.518 110.9,65.518 111.88,66.498 111.88,74.63 111.769,74.74 110.794,74.74 U17.G3@110.527,74.473
DDR_DQS1_N: U10.B18 U17.A7 | length 19.7
  Top Layer w0.09: U10.B18@100.25,78.85 100.624,78.85 100.919,79.145 101.172,79.145 101.217,79.1 102.241,79.1 103.591,80.45 111.569,80.45 112.291,79.729 112.291,76.771 112.404,76.658 112.691,76.658 112.81,76.777 112.81,78.74 113.053,78.983 113.446,78.983 U17.A7@113.73,79.267
DDR_DQS1_P: U10.B19 U17.B7 | length 18.8
  Top Layer w0.09: U10.B19@101.05,78.85 102.344,78.85 103.694,80.2 103.7,80.2 111.466,80.2 112.041,79.625 112.041,76.667 112.3,76.408 112.794,76.408 113.06,76.674 113.06,78.637 113.156,78.733 113.45,78.733 U17.B7@113.728,78.455
DDR_ODT: R258.1 U10.J19 U17.K3 | length 29.9
  Top Layer w0.09: v3(100.65,73.65) U10.J19@101.05,73.25 ; v2@110.125,72.471 U17.K3@110.53,72.067
  Bottom Layer w0.09: v3@100.655,73.645 100.265,73.645 100.195,73.715 100.195,73.819 99.96,74.053 99.74,74.053 99.492,74.302 99.492,76.17 99.827,76.505 99.853,76.505 100.055,76.707 100.055,77.94 102.298,80.184 104.938,80.184 107.01,78.111 107.01,76.206 108.858,74.358 108.858,73.933 109.121,73.67 109.559,73.67 109.747,73.482 109.747,72.823 v2@110.06,72.51 ; R258.1@109.024,79.5 109.234,79.29 109.234,78.65 109.755,78.129 109.755,74.268 110.125,73.898 v2(110.125,72.475)
DDR_RASN: R276.1 U10.J18 U17.L8 | length 26.4
  Top Layer w0.09: v3(99.85,73.65) U10.J18@100.25,73.25 ; U17.L8@114.527,71.273 v2(114.925,71.675)
  Bottom Layer w0.09: v3(99.85,73.65) 100.483,73.017 100.593,73.017 101.29,72.32 101.29,71.977 101.4,71.866 102.109,71.866 102.713,71.262 102.713,70.644 104.153,69.205 105.123,69.205 105.383,68.944 105.383,67.974 106.369,66.988 106.577,66.988 107.075,66.49 110.266,66.49 112.052,68.276 112.052,68.739 112.262,68.949 112.262,69.198 113.296,70.233 113.296,70.359 113.73,70.792 113.73,70.899 ; 113.73,70.9 113.732,70.919 113.732,71.055 113.95,71.273 114.285,71.273 114.685,71.673 v2(114.925,71.675) ; v2@114.925,71.684 115.734,72.493 117.113,72.493 117.63,73.01 R276.1@117.63,73.105
DDR_RESETN: R176.2 U10.E17 U17.P1 | length 24.9
  Top Layer w0.09: U10.E17@99.449,76.451 99.449,76.686 v3@99.553,76.791 ; v2(108.375,75.4) 107.972,75.4 107.322,74.75 107.322,72.449 106.217,71.344 106.217,69.001 106.343,68.874 U17.P1@108.925,68.874
  Bottom Layer w0.09: v3@99.7,76.85 99.733,76.883 99.733,77.131 99.865,77.263 99.865,78.16 102.178,80.474 104.492,80.474 104.509,80.49 104.64,80.49 R176.2@104.85,80.7 ; R176.2@104.85,80.681 107.3,78.231 107.3,76.338 108.263,75.375 v2@108.374,75.375
  other v3: 99.71,76.85
DDR_WEN: R257.1 U10.E18 U17.L2 | length 27.7
  Top Layer w0.09: U10.E18@100.25,76.45 100.575,76.125 v3(100.575,76.05) ; v2@109.327,71.669 U17.L2@109.73,71.267
  Bottom Layer w0.09: v3@100.578,76.05 101.035,76.507 101.035,77.69 102.659,79.314 104.577,79.314 106.103,77.788 106.103,77.385 105.989,77.271 105.989,77.125 106.14,76.974 106.14,76.329 105.989,76.178 105.989,75.997 106.862,75.124 106.862,74.565 106.976,74.451 107.535,74.451 107.77,74.216 107.77,72.489 107.773,72.489 108.02,72.242 108.556,72.242 108.81,71.988 ; 108.81,71.986 108.987,71.986 109.299,71.673 109.327,71.673 109.728,71.272 110.282,71.272 110.567,71.557 110.567,71.822 110.93,72.185 110.93,74.53 111.383,74.983 111.383,77.733 111.575,77.925 111.575,79.125 R257.1@111.925,79.475
  other v2: 109.325,71.675
DSI_CKN: U10.B4 | length 1.6
  Top Layer w0.09: 88.752,80.357 88.752,79.148 U10.B4@89.05,78.85
DSI_CKP: U10.A4 | length 0.8
  Top Layer w0.09: U10.A4@89.05,79.65 89.05,80.464
DSI_D0N: U10.A6 | length 0.8
  Top Layer w0.1: U10.A6@90.65,79.65 90.65,80.443
DSI_D0P: U10.B6 | length 1.7
  Top Layer w0.1: 90.358,80.404 90.358,79.782 90.35,79.774 90.35,79.526 90.358,79.518 90.358,79.142 U10.B6@90.65,78.85
DSI_D1N: U10.A5 | length 0.8
  Top Layer w0.09: U10.A5@89.85,79.65 89.85,80.464
DSI_D1P: U10.B5 | length 1.7
  Top Layer w0.09: 89.562,80.387 89.562,79.779 89.555,79.772 89.555,79.528 89.562,79.521 89.562,79.138 U10.B5@89.85,78.85
DSI_D2N: U10.A3 | length 0.3
  Top Layer w0.09: U10.A3@88.25,79.65 88.25,79.978
DSI_D2P: U10.B3 | length 1.2
  Top Layer w0.09: 87.951,79.877 87.951,79.502 88.25,79.203 U10.B3@88.25,78.85
DSI_D3N: U10.A2 | length 0.8
  Top Layer w0.09: U10.A2@87.45,79.65 87.45,80.464
DSI_D3P: U10.B2 | length 1.7
  Top Layer w0.09: 87.145,80.38 87.145,79.155 U10.B2@87.45,78.85
eMMC.SDMMC2_CK: R49.1 U10.F15 U24.M6 | length 24.8
  Top Layer w0.09: 111.525,86.961 111.525,88.454 111.525,88.502 111.823,88.8 111.825,88.8 111.905,88.88 111.905,89.03 112.325,89.45 v2(112.325,89.475)
  Top Layer w0.11: U10.F15@97.85,75.65 97.85,75.655 v3(98.245,76.05) ; v4(100.675,81.125) 104.15,84.6 109.164,84.6 111.525,86.961 ; v2@112.4,89.475 v2(112.325,89.475) v2@112.4,89.475 ; v2@112.4,89.475 U24.M6@112.775,89.85 v2@112.4,89.475
  Bottom Layer w0.11: v3(98.245,76.05) 98.643,76.449 98.643,79.114 v4@100.675,81.146 ; v2@112.35,89.45 113.05,89.45 R49.1@113.1,89.5
eMMC.SDMMC2_CMD: R37.1 U10.F16 U24.M5 | length 23.7
  Top Layer w0.09: v2(112.3,88.85) 112.3,88.83 112.525,88.605 112.525,86.875
  Top Layer w0.11: U10.F16@98.645,75.65 v3@99.045,76.05 ; v4@102.077,81.623 104.678,84.225 109.875,84.225 112.525,86.875 ; v2(112.3,88.85) 112.3,88.863 112.775,89.338 U24.M5@112.775,89.35
  Bottom Layer w0.11: v3(99.05,76.05) 99.083,76.05 99.355,76.322 99.355,77.04 99.64,77.325 99.64,78.747 100.89,79.996 100.89,80.198 102.048,81.356 102.048,81.598 v4(102.075,81.625) ; v2@112.286,88.836 v2(112.3,88.85) 112.925,88.85 R37.1@113.125,88.65
eMMC.SDMMC2_D0: R44.1 U10.E15 U24.A3 | length 20.8
  Top Layer w0.11: U10.E15@97.85,76.45 v3(98.25,76.85) ; v4(100.675,82.75) 100.275,83.15 100.275,83.6 102.475,85.8 102.475,86.828 102.864,87.217 105.323,87.217 105.507,87.401 105.507,87.807 v4(105.525,87.825) ; v4@105.508,87.833 105.904,88.229 106.797,88.229 106.918,88.35 U24.A3@107.275,88.35
  Bottom Layer w0.11: v3@98.225,76.85 97.884,77.191 97.884,81.18 99.479,82.775 v4@100.65,82.775 ; v4(105.525,87.825) 106.55,88.85 R44.1@106.55,88.9
eMMC.SDMMC2_D1: U10.A15 U24.A4 | length 22.1
  Top Layer w0.11: U10.A15@97.85,79.65 97.85,81.494 99.427,83.071 99.427,83.896 101.62,86.089 101.62,90.695 101.997,91.073 103.155,91.073 103.425,90.803 103.425,88.125 103.55,88 104,88 104.15,88.15 104.15,88.85 104.284,88.984 107.141,88.984 U24.A4@107.275,88.85
eMMC.SDMMC2_D2: U10.C14 U24.A5 | length 22
  Top Layer w0.11: U10.C14@97.05,78.05 97.355,78.355 97.355,79.776 97.327,79.804 97.327,82.377 101.172,86.222 101.172,90.705 102.209,91.741 103.049,91.741 105.583,89.207 107.126,89.207 U24.A5@107.269,89.35
eMMC.SDMMC2_D3: U10.D15 U24.B2 | length 18.7
  Top Layer w0.09: 106.798,87.348 107.05,87.6 107.525,87.6
  Top Layer w0.11: U10.D15@97.85,77.25 v4(98.275,77.675) ; v4(100.95,82.15) 103.804,85.004 107.523,85.004 107.699,85.18 107.699,85.929 106.798,86.831 106.798,87.348 ; 107.525,87.6 U24.B2@107.775,87.85
  Bottom Layer w0.11: v4@98.25,77.675 98.25,81.068 99.249,82.067 v4@100.847,82.067
eMMC.SDMMC2_D4: U10.E14 U24.B3 | length 19.4
  Top Layer w0.09: 107.095,88.1 107.525,88.1
  Top Layer w0.11: U10.E14@97.05,76.45 v4@97.515,76.915 ; v4(100.775,83.425) 102.825,85.475 102.825,86.6 103.006,86.781 105.745,86.781 106,87.036 106,87.75 106.104,87.853 106.848,87.853 107.095,88.1 ; 107.525,88.1 U24.B3@107.775,88.35
  Bottom Layer w0.11: v4@97.425,76.825 97.425,81.2 99.65,83.425 100.75,83.425 v4(100.775,83.425)
  other v4: 97.45,76.825
eMMC.SDMMC2_D5: U10.B15 U24.B4 | length 22.2
  Top Layer w0.09: 106.8,88.6 107.525,88.6
  Top Layer w0.11: U10.B15@97.85,78.85 97.85,79.2 98.155,79.505 98.155,81.315 99.925,83.085 99.925,83.825 102,85.9 102,90.187 102.359,90.546 102.714,90.546 103.09,90.17 103.09,87.844 103.284,87.65 104.3,87.65 104.575,87.925 104.575,88.225 104.948,88.598 106.798,88.598 ; 107.525,88.6 U24.B4@107.775,88.85
eMMC.SDMMC2_D6: U10.A14 U24.B5 | length 22
  Top Layer w0.09: 107.05,89.6 107.525,89.6
  Top Layer w0.11: U10.A14@97.05,79.65 97.05,80.194 ; 97.05,80.2 97.05,82.65 100.8,86.4 100.8,90.842 102.065,92.107 104.526,92.107 105.225,91.408 105.225,90.534 106.314,89.445 106.818,89.445 106.973,89.6 107.05,89.6 ; 107.525,89.6 U24.B5@107.775,89.35
eMMC.SDMMC2_D7: U10.B14 U24.B6 | length 22.9
  Top Layer w0.09: 107.05,90.1 107.382,90.1 107.617,89.865
  Top Layer w0.11: U10.B14@97.05,78.85 96.745,79.155 96.745,80.613 96.704,80.654 96.704,82.829 100.458,86.583 100.458,91.052 101.835,92.43 104.718,92.43 107.048,90.1 ; 107.617,89.865 107.76,89.865 U24.B6@107.775,89.85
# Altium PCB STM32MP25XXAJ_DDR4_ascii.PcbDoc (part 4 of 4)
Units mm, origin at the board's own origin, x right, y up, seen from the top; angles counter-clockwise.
Board outline 172 x 137 mm, 4 copper layers (Top Layer, Signal Layer 1, Signal Layer 2, Bottom Layer), stack 1.614 mm thick; 226 components, 313 nets, 1113 pads, 850 vias.
Unrouted connection lines stored in the file: 13.

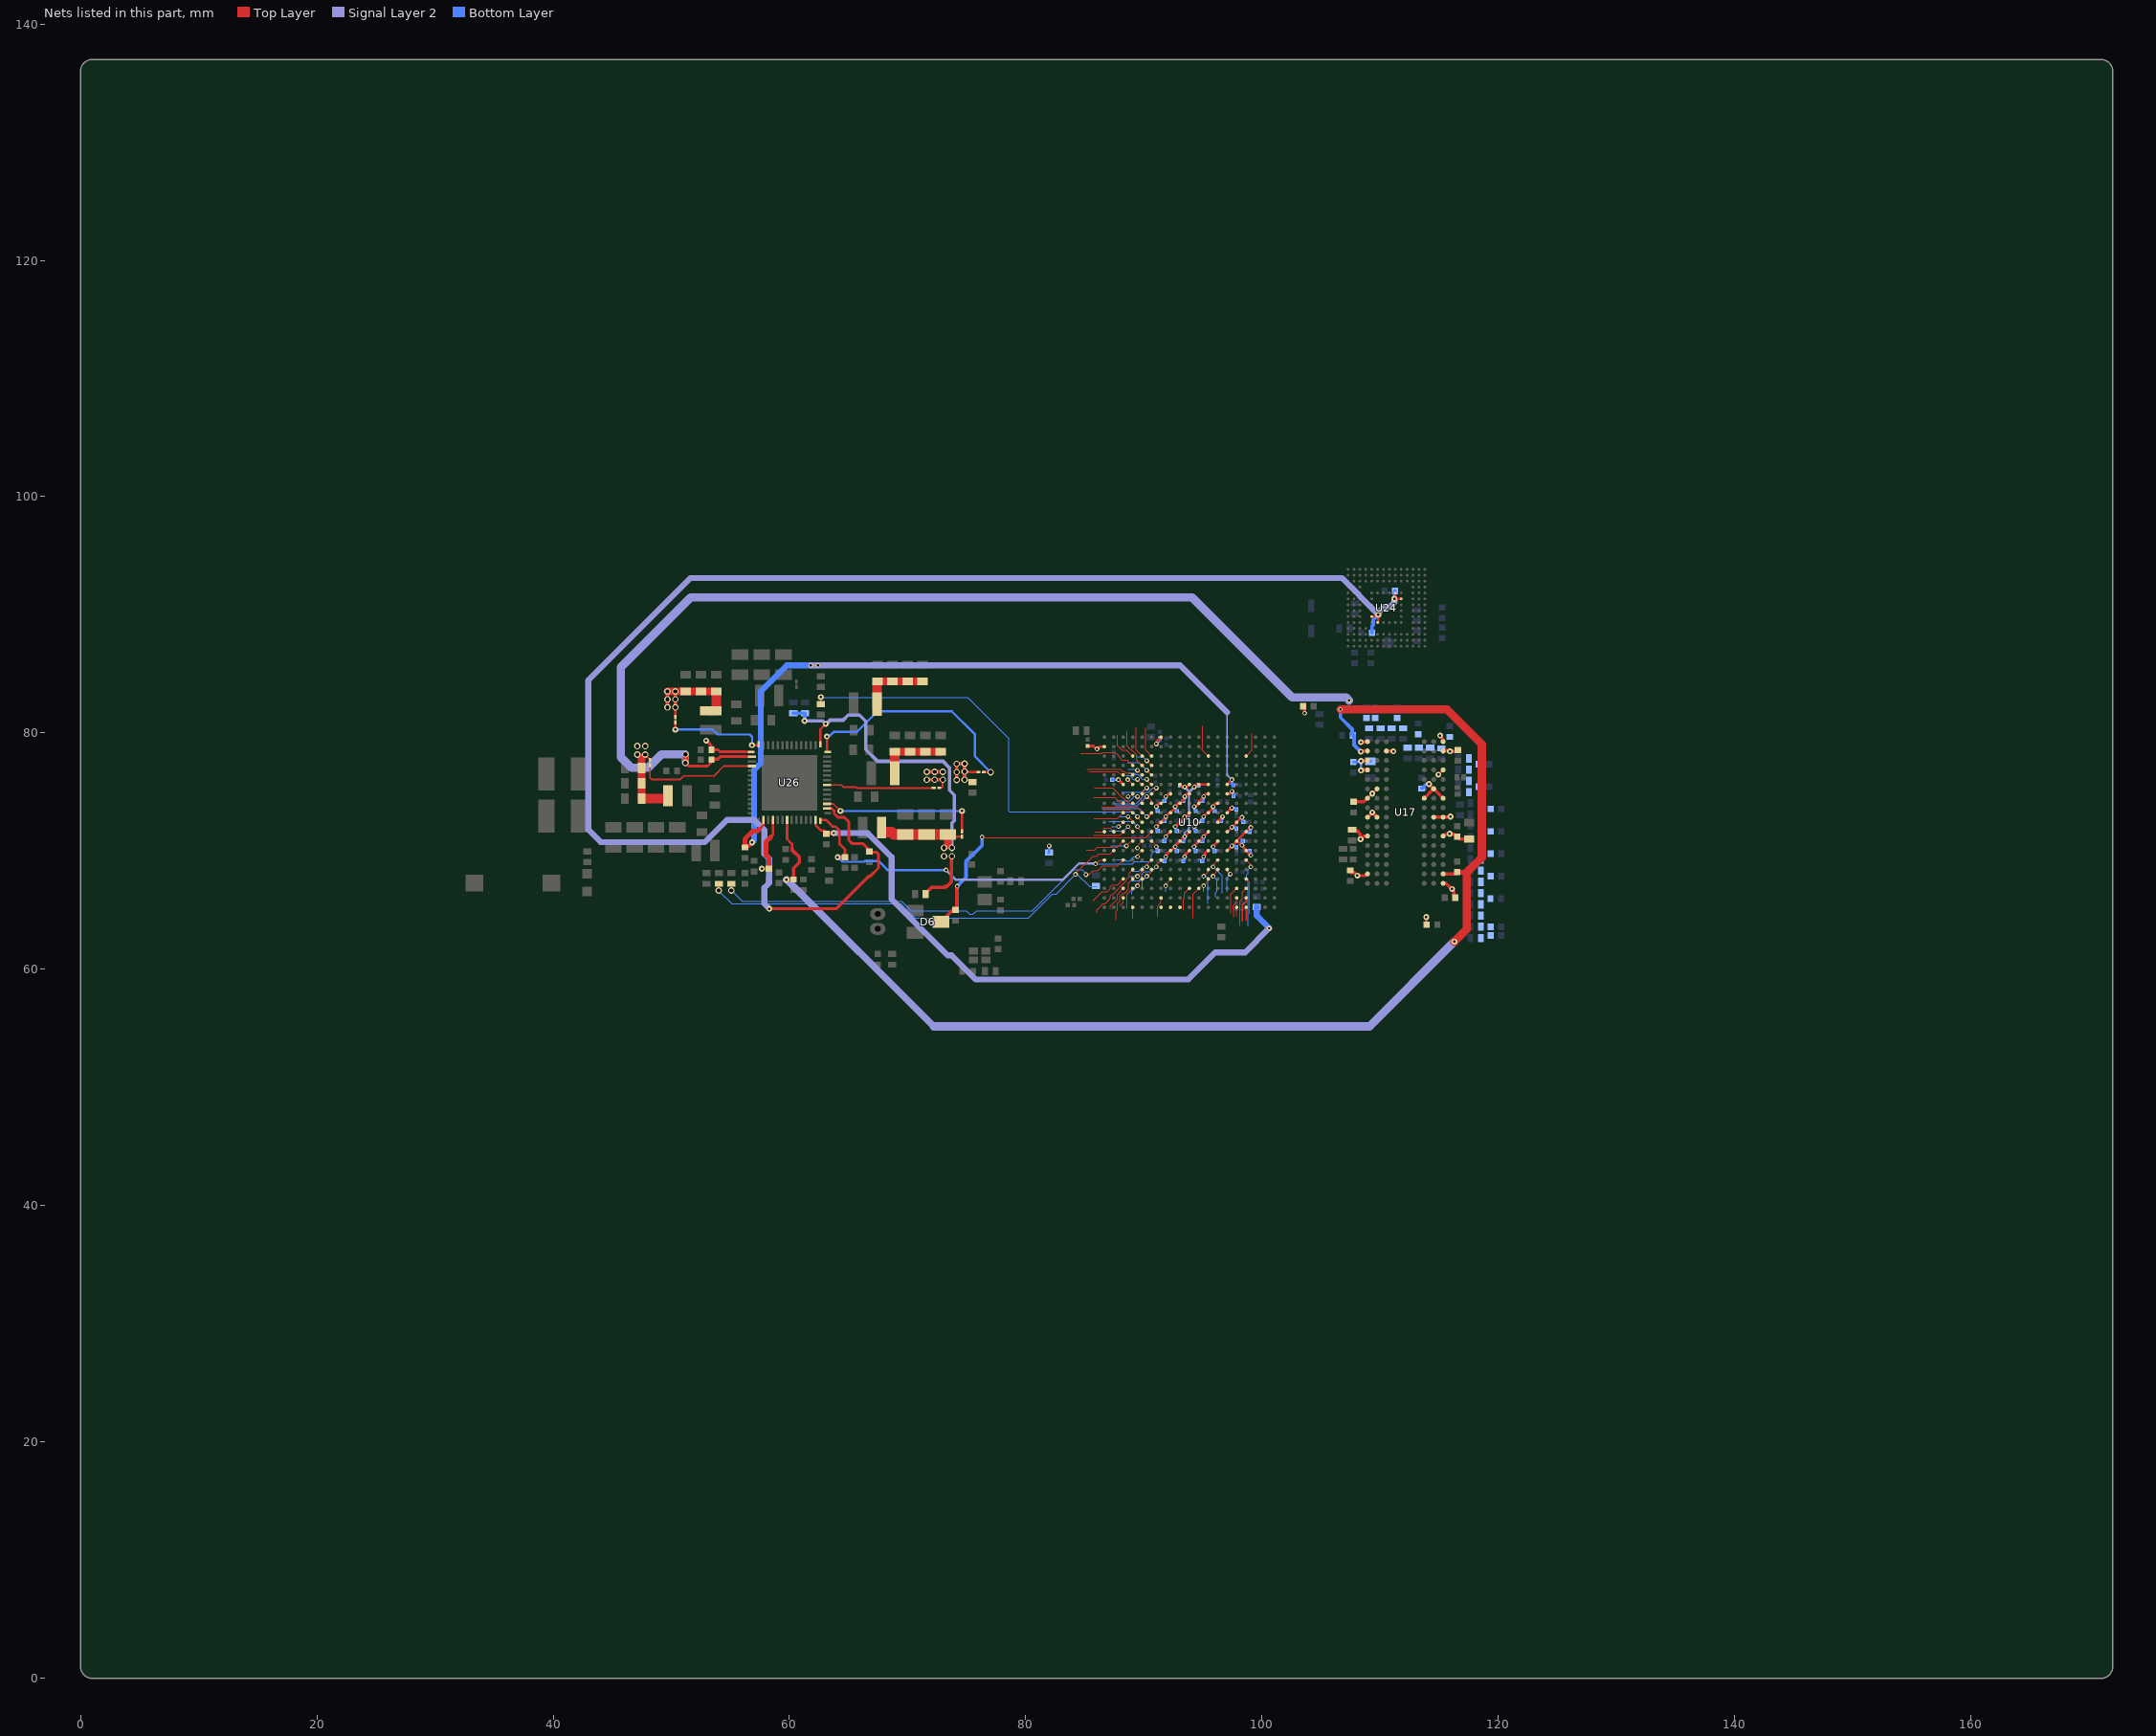
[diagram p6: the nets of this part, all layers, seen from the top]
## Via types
v1: diameter 0.55, hole 0.35, Top Layer to Bottom Layer, 344 vias
v2: diameter 0.5, hole 0.2, Top Layer to Bottom Layer, 250 vias
v3: diameter 0.4, hole 0.2, Top Layer to Bottom Layer, tented both sides, 180 vias
v4: diameter 0.4, hole 0.2, Top Layer to Bottom Layer, 76 vias

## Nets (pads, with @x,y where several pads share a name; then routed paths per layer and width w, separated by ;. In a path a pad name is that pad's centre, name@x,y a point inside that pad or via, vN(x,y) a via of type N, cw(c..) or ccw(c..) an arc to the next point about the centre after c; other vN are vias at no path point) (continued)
PF5: U10.P7 | length 3.5
  Top Layer w0.09: v3@91.046,68.752 91.046,68.802 91.445,69.2 U10.P7@91.445,69.25
  Bottom Layer w0.09: 88.907,67.49 89.572,67.49 89.814,67.732 89.814,68.035 90.041,68.263 90.638,68.263 v3(91.05,68.675)
PF6: U10.R5 | length 1.4
  Top Layer w0.09: v3(89.45,67.875) 89.826,68.251 89.826,68.431 U10.R5@89.845,68.45
  Bottom Layer w0.09: 88.822,67.875 v3(89.45,67.875)
PF7: U10.R6 | length 1.9
  Top Layer w0.09: v3(90.25,67.875) 90.279,67.875 90.641,68.236 90.641,68.441 U10.R6@90.65,68.45
  Bottom Layer w0.09: 89.875,66.925 89.875,67.488 90.25,67.863 v3(90.25,67.875)
PF8: U10.T5 | length 1.5
  Top Layer w0.09: v3@89.45,67.177 89.45,67.213 89.845,67.608 U10.T5@89.845,67.65
  Bottom Layer w0.09: 88.978,66.362 88.978,66.603 v3(89.45,67.075)
PF9: U10.U4 | length 1.9
  Top Layer w0.09: 88.56,65.172 88.56,66.351 89.045,66.836 U10.U4@89.045,66.85
PF10: U10.P6 | length 2
  Top Layer w0.09: v3@90.245,68.85 U10.P6@90.645,69.25
  Bottom Layer w0.09: 88.93,68.33 89.593,68.33 89.938,68.675 v3(90.25,68.675)
PF11: U10.R4 | length 5.1
  Top Layer w0.09: 86.03,64.787 86.03,65.047 86.528,65.545 86.694,65.545 87.155,66.006 87.155,66.207 87.283,66.335 87.369,66.335 87.965,66.931 87.965,66.984 88.336,67.355 88.372,67.355 88.545,67.528 88.545,67.611 88.765,67.831 88.765,68.165 U10.R4@89.05,68.45
PF12: U10.J5 | length 3.6
  Top Layer w0.1: 86.443,73.75 88.829,73.75 88.842,73.737 89.386,73.737 89.845,73.278 U10.J5@89.845,73.25
PF13: U10.G6 | length 4.8
  Top Layer w0.09: U10.G6@90.65,74.85 90.991,75.191 90.991,75.207 91.001,75.218 v3@91.07,75.218
  Bottom Layer w0.09: 87.525,74.04 89.353,74.04 89.905,74.592 89.905,74.768 90.142,75.005 90.393,75.005 90.738,75.35 v3(91.05,75.35)
PF14: U10.F5 | length 1.6
  Top Layer w0.1: v3@89.44,75.968 89.483,75.968 89.802,75.65 U10.F5@89.845,75.65
  Bottom Layer w0.1: 88.487,76.4 88.803,76.4 89.153,76.05 v3@89.45,76.05
  other v3: 89.45,76.075
PF15: U10.G5 | length 3
  Top Layer w0.1: U10.G5@89.85,74.85 89.888,74.888 89.888,74.988 v3(90.25,75.35)
  Bottom Layer w0.1: 88.106,74.984 89.84,74.984 90.206,75.35 v3(90.25,75.35)
PG0: U10.W4 | length 1
  Top Layer w0.09: 89.05,64.282 U10.W4@89.05,65.25
PG1: U10.T3 | length 3.4
  Top Layer w0.09: 85.691,65.784 86.461,66.555 86.825,66.555 86.881,66.555 87.155,66.829 87.155,66.972 87.328,67.145 87.745,67.145 U10.T3@88.25,67.65
PG2: U10.T4 | length 4.1
  Top Layer w0.09: 87.643,64.191 87.643,64.912 87.77,65.04 87.77,65.589 87.95,65.769 87.95,66.167 88.18,66.397 88.337,66.397 88.699,66.759 88.699,67.299 U10.T4@89.05,67.65
PG3: U10.U3 | length 2.2
  Top Layer w0.09: 87.155,65.128 87.155,65.372 87.383,65.6 87.417,65.6 87.75,65.933 87.75,66.347 88.25,66.847 U10.U3@88.25,66.85
PG4: U10.V3 | length 0.8
  Top Layer w0.09: 87.96,65.377 88.253,65.671 88.253,66.047 U10.V3@88.25,66.05
PG5: U10.H3 | length 2.7
  Top Layer w0.09: 85.717,74.539 87.552,74.539 88.034,74.057 88.243,74.057 U10.H3@88.25,74.05
PG6: U10.J3 | length 2.7
  Top Layer w0.09: 85.781,72.75 87.75,72.75 U10.J3@88.25,73.25
PG7: U10.F6 | length 2.4
  Top Layer w0.09: v3@90.239,75.981 90.276,75.981 90.608,75.65 U10.F6@90.645,75.65
  Bottom Layer w0.1: 88.684,76.617 89.188,76.617 89.305,76.5 89.52,76.5 89.8,76.22 89.8,76.134 89.859,76.075 v3(90.25,76.075)
PG8: U10.D4 | length 4.9
  Top Layer w0.1: 84.637,78.268 86.443,78.268 86.526,78.35 87.574,78.35 87.75,78.174 87.75,78.16 87.921,77.989 87.921,77.948 88.143,77.726 88.574,77.726 U10.D4@89.05,77.25
PG9: U10.E4 | length 4.1
  Top Layer w0.1: 85.171,76.95 88.024,76.95 88.224,76.75 88.374,76.75 88.524,76.6 88.9,76.6 U10.E4@89.05,76.45
PG10: U10.E5 | length 1.4
  Top Layer w0.09: v4(89.45,76.85) U10.E5@89.845,76.455
  Bottom Layer w0.09: 88.661,76.922 89.242,76.922 89.255,76.909 89.391,76.909 v4(89.45,76.85)
PG11: U10.E6 | length 2.5
  Top Layer w0.09: v3@90.245,76.85 U10.E6@90.645,76.45
  Bottom Layer w0.09: 88.6,77.5 89.6,77.5 v3(90.25,76.85)
PG12: U10.G4 | length 0.5
  Top Layer w0.1: v4(88.65,74.625) 88.825,74.625 U10.G4@89.05,74.85
PG13: U10.H5 | length 2.7
  Top Layer w0.1: v3(89.45,74.625) 89.825,74.249 89.825,74.075 U10.H5@89.85,74.05
  Bottom Layer w0.1: 87.67,74.275 88.832,74.275 89.168,74.612 89.437,74.612 v3(89.45,74.625)
PG14: U10.E3 | length 2.9
  Top Layer w0.1: 85.427,76.75 87.782,76.75 88.054,76.478 88.222,76.478 U10.E3@88.25,76.45
PG15: U10.C6 | length 2.6
  Top Layer w0.1: 90.15,79.774 90.15,78.726 90.149,78.551 U10.C6@90.65,78.05 ; 90.149,79.775 90.149,80.411
PH2: U10.P13 | length 3.2
  Top Layer w0.09: v3@95.845,68.773 95.845,68.809 96.245,69.209 U10.P13@96.245,69.25
  Bottom Layer w0.09: v3(95.85,68.675) 96.623,67.9 96.623,66.462
PH3: U10.T12 | length 1.2
  Top Layer w0.09: v3@95.05,67.079 95.424,67.453 95.424,67.629 U10.T12@95.445,67.65
  Bottom Layer w0.09: 95.05,66.595 v3(95.05,67.075)
PH4: U10.R13 | length 2.7
  Top Layer w0.09: v3(95.85,67.875) 95.85,67.949 96.089,68.188 96.089,68.282 U10.R13@96.25,68.443
  Bottom Layer w0.09: v3@95.854,67.875 95.854,67.871 96.195,67.53 96.195,66.6 96.045,66.449 96.045,66.12
PH5: U10.R14 | length 2.1
  Top Layer w0.1: U10.R14@97.05,68.45 97.05,68.308 v3(97.3,68.058)
  Bottom Layer w0.1: 97.04,66.575 97.04,67.798 v3(97.3,68.058)
PH6: U10.R12 | length 3.4
  Top Layer w0.09: v3(95.05,67.875) 95.41,68.235 95.41,68.41 U10.R12@95.45,68.45
  Bottom Layer w0.09: v3@95.05,67.97 95.124,67.97 95.43,67.665 95.43,67.082 95.429,67.081 95.429,65.552
PH7: U10.U10 | length 2
  Top Layer w0.09: 93.365,65.05 93.365,65.97 93.445,66.05 93.445,66.45 U10.U10@93.845,66.85
PH8: U10.U11 | length 2.7
  Top Layer w0.09: 94.152,64.354 94.152,66.358 U10.U11@94.645,66.85
PH9: U10.T8 | length 1.1
  Top Layer w0.09: v3@91.893,67.187 91.893,67.24 92.245,67.591 U10.T8@92.245,67.65
  Bottom Layer w0.09: 91.85,66.571 v3(91.85,67.075)
PH10: U10.W9
PH11: U10.W8
PH12: U10.V7 | length 1.7
  Top Layer w0.09: 91.15,64.445 91.15,65.372 91.445,65.667 U10.V7@91.445,66.05
PH13: U10.W7
PI0: U10.D6 | length 1.6
  Top Layer w0.1: v3@90.245,77.65 U10.D6@90.645,77.25
  Bottom Layer w0.1: 89.354,78.006 89.894,78.006 v3(90.25,77.65)
PI1: U10.F4 | length 0.6
  Top Layer w0.1: v4(88.632,76.05) 89.057,75.625 U10.F4@89.075,75.625
PI2: U10.J6 | length 4.6
  Top Layer w0.22: v3@90.259,72.838 90.259,72.848 90.645,73.234 U10.J6@90.645,73.25
  Bottom Layer w0.09: 86.463,73.597 89.578,73.597 v3(90.25,72.925)
PI3: U10.H4 | length 3.8
  Top Layer w0.09: 85.8,75.35 87.357,75.35 87.562,75.145 87.572,75.145 87.85,74.867 87.85,74.833 88.178,74.505 88.282,74.505 88.507,74.28 88.513,74.28 88.743,74.05 U10.H4@89.05,74.05
PI4: U10.H6 | length 3.8
  Top Layer w0.09: v3(90.25,74.625) 90.28,74.625 90.641,74.264 90.641,74.059 U10.H6@90.65,74.05
  Bottom Layer w0.09: 87.551,73.85 89.475,73.85 v3(90.25,74.625)
PI5: U10.D5 | length 3.5
  Top Layer w0.1: 88.554,80.166 88.554,78.936 88.75,78.74 88.75,78.726 88.923,78.553 88.957,78.553 89.16,78.35 89.174,78.35 89.39,78.134 89.39,77.71 U10.D5@89.85,77.25
PI6: U10.C5 | length 2.6
  Top Layer w0.1: 89.354,80.457 89.354,78.546 U10.C5@89.85,78.05
PI7: U10.C4 | length 2.5
  Top Layer w0.1: 87.756,79.813 87.756,78.933 87.95,78.74 87.95,78.726 88.116,78.56 88.54,78.56 U10.C4@89.05,78.05
PI8: U10.N5 | length 2.5
  Top Layer w0.09: v3@89.445,69.65 U10.N5@89.845,70.05
  Bottom Layer w0.09: 87.666,69.285 88.397,69.285 88.502,69.18 88.788,69.18 89.133,69.525 v3(89.45,69.525)
PI9: U10.J4 | length 2.6
  Top Layer w0.1: 86.526,73.55 88.746,73.55 89.046,73.25 U10.J4@89.05,73.25
PI10: U10.C12 | length 2.8
  Top Layer w0.1: 94.95,80.573 94.95,78.726 94.925,78.701 94.925,78.575 U10.C12@95.45,78.05
PI11: U10.C16 | length 2.1
  Top Layer w0.09: U10.C16@98.65,78.05 99.15,78.55 99.15,79.947
PMIC_WAKEUPn: R46.1 U10.K5 | length 35.7
  Top Layer w0.1: v3@89.445,72.85 U10.K5@89.845,72.45
  Top Layer w0.15: R46.1@62.65,82.448 v2(62.65,83.033)
  Bottom Layer w0.1: v2@62.703,83.022 75.078,83.022 78.559,79.541 78.559,73.388 78.617,73.33 89.045,73.33 v3(89.45,72.925)
PWR_CPU_ON: R60.1 R272.2 U10.N2 | length 39.6
  Top Layer w0.1: v1@54.014,66.64 54.014,67.229 R60.1@54.03,67.245 ; v4(84.214,68.036) 84.214,68.097 85.696,69.578 86.004,69.578 86.186,69.76 87.16,69.76 U10.N2@87.45,70.05
  Bottom Layer w0.1: v1(54.009,66.67) 55.107,65.572 69.42,65.572 70.634,64.358 78.204,64.358 80.233,64.358 82.263,66.387 82.587,66.387 84.214,68.014 v4(84.214,68.036) 84.38,68.036 85.416,67 R272.2@86,67
PWR_ON: R2.1 U10.P3 | length 36.9
  Top Layer w0.1: v1@55.08,66.64 R2.1@55.08,67.245 ; v4(85.1,68.025) 85.117,68.042 85.378,68.042 85.678,68.342 86.117,68.342 86.525,68.75 87.75,68.75 U10.P3@88.25,69.25
  Bottom Layer w0.1: v1(55.075,66.67) 55.119,66.67 56.017,65.772 69.502,65.772 70.317,64.957 74.948,64.957 75.255,64.65 75.545,64.65 75.853,64.957 80.55,64.957 84.018,68.425 84.775,68.425 v4@85.125,68.075
PZ0: U10.L5 | length 3.1
  Top Layer w0.1: v3@89.445,71.95 89.495,71.95 89.795,71.65 U10.L5@89.845,71.65
  Bottom Layer w0.1: 87.046,72.503 89.022,72.503 v3(89.45,72.075)
PZ1: U10.M3 | length 3.4
  Top Layer w0.09: 85.131,70.113 85.829,70.113 86.069,70.354 87.754,70.354 U10.M3@88.25,70.85
PZ2: U10.L3 | length 2.7
  Top Layer w0.09: 85.725,71.346 87.946,71.346 U10.L3@88.25,71.65
PZ3: U10.M5 | length 0.8
  Top Layer w0.1: v4(89.45,70.256) 89.507,70.314 89.507,70.507 U10.M5@89.85,70.85
PZ4: U10.L4 | length 2.3
  Top Layer w0.1: v3@88.648,72.031 88.659,72.031 89.039,71.65 U10.L4@89.045,71.65
  Bottom Layer w0.1: 87.041,71.714 88.289,71.714 v3(88.65,72.075)
PZ5: U10.M4 | length 2.1
  Top Layer w0.1: v3(88.525,70.45) 88.887,70.812 89.006,70.812 U10.M4@89.045,70.85
  Bottom Layer w0.1: 87.179,70.35 87.279,70.45 v3(88.525,70.45)
PZ6: U10.K4 | length 1.4
  Top Layer w0.1: v3(88.65,72.925) 89.05,72.525 U10.K4@89.05,72.45
  Bottom Layer w0.1: 87.9,72.925 v3(88.65,72.925)
PZ7: U10.L2 | length 1
  Top Layer w0.09: 86.54,71.975 87.125,71.975 U10.L2@87.45,71.65
PZ8: U10.K3 | length 1.2
  Top Layer w0.1: v4@87.851,72.06 87.86,72.06 U10.K3@88.25,72.45
  Bottom Layer w0.1: 87.223,72.075 v4(87.851,72.075)
PZ9: U10.L1 | length 0.8
  Top Layer w0.09: 85.875,71.65 U10.L1@86.65,71.65
UCPD1_CC1: U10.P16 | length 5.9
  Top Layer w0.09: U10.P16@98.65,69.25 99.05,68.85 v3(99.05,68.675)
  Bottom Layer w0.1: 98.8,63.713 98.8,67.63 98.7,67.73 98.7,68.02 98.8,68.12 98.8,68.425 v3(99.05,68.675)
UCPD1_CC2: U10.U15 | length 2.3
  Top Layer w0.1: 97.35,64.733 97.35,65.475 97.375,65.5 97.375,66.375 U10.U15@97.85,66.85
USB3DR_DM: U10.V16 | length 2.1
  Top Layer w0.11: 98.345,64.047 98.345,65.423 98.645,65.723 U10.V16@98.645,66.05
USB3DR_DP: U10.W16 | length 1.1
  Top Layer w0.11: 98.645,64.15 U10.W16@98.645,65.25
USB3DR_TXRTUNE: U10.T16 | length 3.1
  Top Layer w0.1: U10.T16@98.65,67.65 98.95,67.35 98.95,64.709
USBH_HS_DM: U10.V15 | length 1.8
  Top Layer w0.1: 97.594,64.438 97.594,65.082 97.55,65.126 97.55,65.392 97.85,65.692 U10.V15@97.85,66.05
USBH_HS_DP: U10.W15 | length 0.8
  Top Layer w0.09: 97.85,64.45 U10.W15@97.85,65.25
USBH_HS_TXRTUNE: U10.U16 | length 3.4
  Top Layer w0.1: 98.14,63.692 98.14,65.775 98.344,65.979 98.344,66.544 U10.U16@98.65,66.85
VBAT: C87.2 D6.3 U10.L6 | length 23.9
  Top Layer w0.09: v4(76.3,71.2) 76.344,71.156 90.156,71.156 U10.L6@90.65,71.65
  Top Layer w0.3: D6.3@73.2,64.375 72.85,64.025 D6.3@72.825,64.025 73.825,65.025 C87.2@74.05,65.025 ; C87.2@73.925,65.125 74.173,65.125 74.178,65.13 74.178,67.011 v3(74.197,67.03)
  Bottom Layer w0.3: v3(74.197,67.03) 74.952,67.785 74.952,69.133 76.3,70.481 v4(76.3,71.2)
VDD3V3_USB: C156.2 R197.1 U26.13 | length 50.4
  Top Layer w0.21: U26.13@62.2,72.63 62.2,72.2 62.663,71.737 62.918,71.737 62.92,71.735 62.99,71.735 63.125,71.6 C156.2@63.125,71.53
  Top Layer w0.3: C156.2@63.125,71.53 v2(63.735,71.53)
  Signal Layer 2 w0.5: v2(63.735,71.53) 66.62,71.53 68.65,69.5 68.65,65.93 73.395,61.185 73.717,61.185 75.752,59.15 93.752,59.15 96.035,61.433 98.571,61.433 v4(100.611,63.473)
  Bottom Layer w0.5: R197.1@99.55,65.275 99.55,64.534 v4@100.591,63.494
VDD_DDR: C39.2 C41.2 C70.2 C82.2 C104.2 C105.2 C106.2 C112.2 C172.2 C175.2 C176.2 C178.2 C179.2 C181.2 C195.2 C200.2 C201.2 C202.2 C218.2 C377.2 C383.2 C386.2 C389.1 L5.2 LNK8.2 R116.1 U10.G14 U10.J14 U10.K15 U10.L14 U10.L16 U10.M15 U10.N14 U10.N16 U17.A1 U17.A9 U17.B3 U17.B9 U17.C1 U17.D1 U17.D9 U17.F2 U17.F8 U17.G1 U17.G7 U17.G9 U17.J1 U17.J2 U17.J8 U17.J9 U17.L1 U17.L9 U17.R1 U17.T9 U26.43 | length 45.7
  Top Layer w0.15: v1(47.798,78.165) 48.2,77.763 LNK8.2@48.2,77.723
  Top Layer w0.2: U17.J1@108.927,72.873 U17.J1@108.95,72.873 ; U17.G1@108.969,74.515 109.312,74.858 v2@109.316,74.858 ; v2@109.325,74.85 109.325,74.871 U17.F2@109.727,75.273 ; v2@109.327,73.25 v2@109.327,73.273
  Top Layer w0.21: 56.275,78.4 U26.43@56.825,78.4
  Top Layer w0.22: U10.N14@97.05,70.05 v3(97.45,70.45) ; U10.L14@97.05,71.65 97.072,71.65 97.112,71.69 97.118,71.69 v3@97.45,72.022 ; U10.J14@97.05,73.25 97.3,73.5 v4@97.3,73.65 ; U10.G14@97.05,74.85 97.24,74.85 v3(97.45,75.06) ; v3(97.45,72.025) U10.K15@97.85,72.425 ; v3@97.456,70.45 U10.M15@97.85,70.844 ; U10.M15@97.85,70.85 97.872,70.85 97.912,70.81 97.94,70.81 v3@98.16,70.59 ; U10.K15@97.85,72.45 v3@98.25,72.85 ; U10.M15@97.875,70.875 U10.L16@98.65,71.65 98.966,71.966 99.016,71.966 v3(99.05,72) ; v3@98.161,70.59 98.251,70.5 v3(98.3,70.5) 98.3,70.461 98.635,70.126 98.635,70.065 U10.N16@98.65,70.05 v3(99.05,69.65) ; C70.2@103.475,82.25 103.575,82.15 v4@103.575,81.625 ; v2(114.925,76.475) U17.D9@115.325,76.875
  Top Layer w0.25: 53.195,79.125 53.199,79.125 53.345,78.979 53.345,78.685 C39.2@53.455,78.575 ; C39.2@53.505,78.575 53.975,78.575 54.15,78.4 56.275,78.4
  Top Layer w0.28: C104.2@107.397,68.308 107.512,68.193 107.788,68.193 108.053,67.928 108.744,67.928 108.889,68.073 U17.R1@108.927,68.073 ; R116.1@107.625,71.81 107.74,71.695 108.071,71.695 108.293,71.474 108.293,71.042 108.342,70.993 108.609,71.26 108.909,71.26 U17.L1@108.925,71.275 ; C105.2@107.737,74.178 108.632,74.178 U17.G1@108.969,74.515 ; v2@108.338,79.225 108.348,79.235 108.851,79.235 108.862,79.246 108.9,79.246 U17.A1@108.927,79.273 ; v2@109.327,73.273 U17.J2@109.727,72.873 ; U17.B3@110.525,78.475 110.537,78.463 v2@111.087,78.463 ; U17.G7@113.725,74.475 U17.F8@114.502,75.253 ; C82.2@113.902,63.768 v2@113.902,64.413 ; v2(114.125,75.675) 114.5,75.3 U17.F8@114.525,75.3 ; U17.J8@114.528,72.842 U17.J8@114.553,72.842 ; U17.J8@114.527,72.873 115.327,72.873 U17.J9@115.333,72.866 ; U17.F8@114.527,75.273 114.892,74.908 114.902,74.908 ; 114.963,74.837 115.327,74.473 U17.G9@115.325,74.475 ; v2@115.067,79.78 115.067,79.72 115.3,79.487 115.3,79.275 U17.A9@115.327,79.248 ; U17.T9@115.325,67.275 115.351,67.248 115.576,67.248 116.024,66.8 v2(116.075,66.8) 116.075,66.74 116.235,66.581 116.235,66.19 116.327,66.098 C106.2@116.347,66.098 ; U17.J9@115.325,72.875 115.9,72.875 v2(115.95,72.925) ; U17.L9@115.327,71.273 115.354,71.273 115.515,71.435 115.838,71.435 v2@115.877,71.473 ; U17.B9@115.327,78.473 115.353,78.5 115.831,78.5 115.914,78.417 v2@115.974,78.417 ; U17.A9@115.327,79.273 U17.A9@115.327,79.277 ; v2@115.877,71.419 v2@115.877,71.473 ; v2(115.9,78.45) 116.45,78.45 C178.2@116.6,78.6 ; C178.2@116.575,78.55 C178.2@116.6,78.55 ; C112.2@117.547,71.028 116.732,71.028 116.542,71.218 116.492,71.218 116.279,71.431 115.919,71.431 v2@115.877,71.473
  Top Layer w0.3: v2@52.944,79.376 53.195,79.125 ; v2@108.377,76.873 U17.D1@108.927,76.873 ; v2@108.377,77.673 U17.C1@108.927,77.673 ; U17.J1@108.95,72.873 v2@109.327,73.25
  Top Layer w0.64: C202.2@47.475,74.45 C41.2@47.475,75.75 C200.2@47.475,77.05 ; 47.475,77.495 47.475,77.925
  Top Layer w0.8: C202.2@47.7,74.45 L5.2@49.475,74.45
  Bottom Layer w0.22: v4(97.45,73.65) 97.7,73.65 C201.2@97.825,73.525 ; v3(97.45,70.45) 97.7,70.45 C386.2@97.825,70.325 ; v3(97.45,72.025) 97.7,72.025 C377.2@97.8,71.925 ; v3(97.45,75.06) 97.575,74.935 97.575,74.675 C176.2@97.575,74.65 ; v3@98.25,70.5 98.25,70.75 C389.1@98.375,70.875 ; v3(98.3,72.85) 98.3,72.575 C175.2@98.4,72.475 ; C195.2@98.925,70.025 99.05,69.9 v3(99.05,69.65) ; C383.2@98.925,71.625 99.05,71.75 v3(99.05,72) ; C218.2@107.725,77.55 108.325,77.55 v2@108.375,77.6 ; v2@108.4,76.8 v2(108.375,76.825) v2@108.375,77.6 ; C172.2@109.175,77.6 109.15,77.625 v2@108.4,77.625 ; v2@108.375,77.6 v2@108.4,77.625 ; v2@108.375,77.6 v2(108.375,77.625) v2@108.4,77.625
  Bottom Layer w0.28: C179.2@113.5,75.3 113.875,75.675 v2(114.125,75.675) v2@114.15,75.675
  other v1: 47.123,78.165 47.123,78.89 47.798,78.89
  other v2: 113.895,64.42 108.06,67.93 108.335,71.015 115.875,71.475 109.325,73.275 109.325,74.875 111.11,78.45 108.365,79.225 52.95,79.348 115.065,79.782
  other v4: 103.6,81.675
VDD_DDR_FB: LNK8.1 U26.46 | length 10.2
  Top Layer w0.15: LNK8.1@48.2,77.273 48.2,76.19 48.317,76.073 50.767,76.073 51.067,76.373 51.737,76.373 51.739,76.375 53.627,76.375 54.452,77.2 U26.46@56.83,77.2
VDD_EMMC: C177.2 C180.2 C190.1 U24.E6 U24.F5 U24.J10 U24.K9 U26.16 | length 133.5
  Top Layer w0.18: U24.E6@109.275,89.85 109.58,89.85 109.73,90 v2(109.825,90) ; U24.F5@109.775,89.35 109.775,89.358 109.825,89.408 v2@109.825,89.85 ; v2@111.2,91.25 v2@111.275,91.325 ; U24.J10@111.275,91.85 111.275,91.42 111.267,91.412 111.267,91.333 v2@111.275,91.325 ; U24.K9@111.775,91.35 111.395,91.35 111.362,91.317 111.283,91.317 v2@111.275,91.325
  Top Layer w0.21: U26.16@63.17,73.6 63.6,73.6 63.788,73.412 63.788,73.188 63.934,73.041
  Top Layer w0.25: v2(58.3,65.125) 63.96,65.125 66.7,67.865 66.822,67.865 67.535,68.578 67.535,69.764 67.389,69.91 66.805,69.91 C190.1@66.75,69.965 ; 63.932,73.038 64.098,72.872 64.628,72.872 65.025,72.475 65.025,70.925 65.3,70.65 66.195,70.65 C190.1@66.75,70.095
  Signal Layer 2 w0.5: v2@58.31,65.125 57.882,65.553 57.882,66.908 58.275,67.301 58.275,69.369 57.882,69.762 57.882,71.786 57.019,72.649 54.713,72.649 52.837,70.773 44.034,70.773 42.968,71.839 42.968,84.457 51.626,93.115 106.736,93.115 v2@109.688,90.163 ; v2@109.835,90 109.845,90.01 109.845,90.196 110.269,90.62 110.485,90.62 110.747,90.62 111.21,91.083 v2@111.21,91.25
  Bottom Layer w0.3: C180.2@109.3,88.475 109.3,89.049 109.4,89.149 109.4,89.575 v2(109.825,90) ; v2@111.2,91.25 111.225,91.275 111.225,92 C177.2@111.25,92.025
  other v2: 111.2,91.35
VDD_SDCARD: C142.1 U26.4 | length 5.1
  Top Layer w0.21: 58.425,71.2 58.6,71.375 U26.4@58.6,72.63
  Top Layer w0.3: v2(57.665,68.51) C142.1@58.275,68.51
  Top Layer w0.4: C142.1@58.275,68.51 58.275,69.393 58.01,69.658 58.01,70.785 58.425,71.2
VDDA1V8_AON: C189.2 C393.2 U10.M6 U10.P1 U26.14 | length 36.2
  Top Layer w0.1: v4@85.9,68.875 86.275,69.25 U10.P1@86.65,69.25 ; U10.M6@90.65,70.85 91.025,70.475 v3@91.025,70.375
  Top Layer w0.21: U26.14@62.6,72.63 63.11,72.63 63.648,72.092 63.887,72.092 64.245,71.734 64.245,70.602 64.7,70.147 C189.2@64.7,69.49
  Top Layer w0.3: v2(64.09,69.49) C189.2@64.7,69.49
  Signal Layer 2 w0.2: v3(73.253,68.406) 73.259,68.406 74.065,67.6 83.15,67.6 84.519,68.97 85.689,68.97 85.741,68.918 85.868,68.918 v4@85.906,68.88
  Bottom Layer w0.1: v4@85.906,68.88 85.953,68.927 89.027,68.927 89.205,69.106 90.456,69.106 90.64,69.29 90.64,69.739 90.897,69.995 C393.2@91.104,69.995
  Bottom Layer w0.12: v3(91.05,70.375) v3@91.104,70.321 ; C393.2@91.104,70.071 C393.2@91.175,70
  Bottom Layer w0.2: v2(64.09,69.49) 64.48,69.1 66.321,69.1 66.392,69.171 67.535,69.171 68.3,68.406 v3(73.253,68.406) ; C393.2@91.104,70.071 v3@91.104,70.321
  other v4: 85.9,68.925
VDDCORE: C22.2 C23.2 C24.2 C161.2 C164.1 C166.2 C167.2 C169.2 C173.1 C183.2 C353.2 C355.2 C372.2 C378.2 C390.2 L2.2 LNK2.2 R199.1 U10.A7 U10.B1 U10.F3 U10.G8 U10.G10 U10.H7 U10.H9 U10.J8 U10.J10 U10.K7 U10.K9 | length 24.8
  Top Layer w0.09: v3@91.89,74.475 v3@91.89,74.485
  Top Layer w0.2: C22.2@71.275,84.375 C22.2@71.323,84.423 ; v1@74.87,76.685 LNK2.2@75.98,76.685
  Top Layer w0.22: C353.2@85.225,78.9 85.73,78.9 85.998,78.632 86.088,78.632 86.291,78.835 86.635,78.835 U10.B1@86.65,78.85 ; v4(87.825,76.05) 87.825,76.038 88.044,75.82 88.08,75.82 U10.F3@88.25,75.65 ; v3(91.05,72.075) 91.063,72.075 91.438,72.45 U10.K7@91.445,72.45 ; v3(91.05,73.775) 91.05,73.822 91.252,74.025 91.425,74.025 U10.H7@91.45,74.05 ; v4@91.05,79.056 91.084,79.091 91.084,79.284 U10.A7@91.45,79.65 ; U10.K7@91.458,72.45 91.816,72.807 91.816,72.891 v3(91.85,72.925) 91.85,72.953 92.107,73.21 92.21,73.21 U10.J8@92.25,73.25 92.65,73.65 v3(92.65,73.775) v3@92.65,73.779 ; v3(91.85,74.625) 91.884,74.625 92.094,74.835 92.246,74.835 U10.G8@92.25,74.839 ; v3(92.65,72.075) 92.675,72.075 U10.K9@93.05,72.45 93.05,72.472 93.09,72.512 93.09,72.545 v3@93.45,72.905 ; v3@92.65,73.8 v3@92.65,73.779 ; v3(93.45,72.925) 93.484,72.959 93.56,72.959 U10.J10@93.85,73.25 ; U10.G10@93.845,74.85 93.624,74.85 93.45,74.676 v3(93.45,74.625) 93.45,74.45 U10.H9@93.05,74.05 93.035,74.035 92.906,74.035 v3@92.65,73.779
  Top Layer w0.3: v1@74.151,77.404 v1(74.826,77.404) v1(74.826,76.729) ; v1(74.156,76.024) v1(74.156,76.699) v1(74.156,77.374) ; v1(74.826,76.054) v1(74.826,76.729) ; v1@74.87,76.685 v1(74.826,76.729)
  Top Layer w0.64: C183.2@67.45,84.375 C24.2@68.725,84.375 C23.2@70,84.375 C22.2@71.275,84.375
  Top Layer w0.8: L2.2@67.415,82.2 L2.2@67.415,82.45 C183.2@67.415,84.173
  Bottom Layer w0.2: C161.2@87.325,76.05 v4(87.825,76.05) ; v4(91.05,79.075) 91.275,79.3 91.275,79.475 C355.2@91.35,79.55
  Bottom Layer w0.22: v3(91.05,72.075) 91.05,71.825 C378.2@91.175,71.7 ; v3(91.05,73.775) 91.05,73.55 C173.1@91.175,73.425 ; C169.2@91.725,72.55 91.85,72.675 v3(91.85,72.925) ; C166.2@91.725,74.275 91.85,74.4 v3(91.85,74.625) ; v3(92.65,72.075) 92.65,71.825 C372.2@92.775,71.7 ; v3(92.65,73.775) 92.65,73.525 C167.2@92.775,73.4 ; C164.1@93.325,72.55 93.45,72.675 v3(93.45,72.925) ; C390.2@93.35,74.275 93.45,74.375 v3(93.45,74.625)
  other v4: 86.025,78.65
VDDCORE_FB: LNK2.1 U26.28 | length 19.9
  Top Layer w0.2: U26.28@63.17,78.4 v2(63.17,79.7) ; LNK2.1@76.444,76.687 v1@77.031,76.685
  Bottom Layer w0.2: v2(63.17,79.7) 63.227,79.757 63.401,79.757 63.754,80.111 65.734,80.111 67.457,81.833 73.744,81.833 75.675,79.902 75.675,78.041 v1(77.033,76.683)
VDDCPU: C26.2 C27.2 C28.2 C159.2 C163.2 C168.2 C174.1 C360.1 L3.2 LNK4.1 U10.G12 U10.H11 U10.H13 U10.J12 U10.K13 | length 16.3
  Top Layer w0.2: LNK4.1@50.35,81.35 v1(50.35,82.173)
  Top Layer w0.22: v3(94.25,73.775) 94.284,73.809 94.437,73.809 94.61,73.982 94.61,73.988 94.65,74.028 94.65,74.2 v3@95.075,74.625 ; v3@95.05,72.93 95.355,73.235 95.435,73.235 U10.J12@95.45,73.25 95.875,73.675 v3@95.875,73.697 ; v3(95.05,74.625) 95.05,74.64 95.249,74.839 95.434,74.839 U10.G12@95.445,74.85 ; v3(95.85,73.775) 95.85,73.816 96.055,74.022 96.216,74.022 U10.H13@96.245,74.05 ; U10.K13@96.25,72.45 96.265,72.465 96.265,72.523 v3@96.65,72.907
  Top Layer w0.3: v1(49.675,82.173) v1(49.675,82.848) v1(49.675,83.523) v1(50.35,83.523) v1(50.35,82.848) v1(50.35,82.173)
  Top Layer w0.64: v1(49.675,83.523) 49.675,83.525 C27.2@51.2,83.525 C28.2@52.5,83.525 C26.2@53.8,83.525
  Top Layer w0.8: L3.2@53.35,81.875 53.8,81.875 53.8,83.173
  Bottom Layer w0.22: v3(94.25,73.775) 94.25,73.525 C159.2@94.375,73.4 ; C168.2@94.925,72.525 95.05,72.65 v3(95.05,72.925) ; C360.1@94.925,74.25 95.05,74.375 v3(95.05,74.625) ; v3(95.85,73.775) 95.85,73.525 C174.1@95.975,73.4 ; C163.2@96.5,72.55 96.65,72.7 v3(96.65,72.925)
VDDCPU_FB: LNK4.2 U26.42 | length 8.6
  Top Layer w0.2: v2(50.35,80.29) LNK4.2@50.35,80.9 ; v2(56.825,78.975) U26.42@57.395,78.975
  Bottom Layer w0.2: v2@50.37,80.287 53.499,80.287 53.914,79.872 56.643,79.872 56.845,79.67 v2@56.845,78.972
VDDGPU: C34.2 C35.2 C36.2 C37.2 C191.1 C381.2 C382.2 C388.2 C402.2 L4.2 LNK7.2 U10.K11 U10.L12 U10.M11 U10.M13 U10.N12 | length 14.9
  Top Layer w0.15: LNK7.2@72.675,75.35 72.682,75.358 72.885,75.358 72.973,75.445 v1(72.973,76.038)
  Top Layer w0.2: C35.2@73.05,78.393 C35.2@73.098,78.345
  Top Layer w0.22: v3(94.25,70.375) 94.25,70.45 U10.M11@94.65,70.85 95.025,71.225 v3(95.05,71.225) ; v3@94.27,72.075 U10.K11@94.645,72.45 ; v3(95.05,69.525) 95.2,69.675 95.2,69.844 95.406,70.05 U10.N12@95.445,70.05 ; v3(95.85,70.375) 95.85,70.412 96.245,70.807 U10.M13@96.245,70.85
  Top Layer w0.24: v3@95.05,71.25 U10.L12@95.45,71.65
  Top Layer w0.3: v1(71.623,76.038) v1(72.298,76.038) v1(72.973,76.038) ; v1(71.623,76.713) v1(72.298,76.713) v1(72.973,76.713) ; v3(95.05,71.225) v3@95.05,71.25
  Top Layer w0.64: C37.2@68.9,78.4 C36.2@70.2,78.4 C34.2@71.5,78.4 C35.2@72.8,78.4
  Top Layer w0.8: L4.2@68.925,76.6 68.925,78.073
  Bottom Layer w0.22: v3(94.25,70.375) 94.25,70.125 C381.2@94.375,70 ; v3(94.25,72.075) 94.25,71.825 C388.2@94.375,71.7 C388.2@94.4,71.675 ; C402.2@94.925,69.15 95.05,69.275 v3(95.05,69.525) ; v3(95.85,70.375) 95.85,70.125 C191.1@95.975,70
  Bottom Layer w0.24: C382.2@94.925,70.85 95.05,70.975 v3(95.05,71.225)
  Bottom Layer w0.3: v3@94.2,70.4 v3@94.225,70.4
VDDGPU_FB: LNK7.1 U26.21 | length 9.3
  Top Layer w0.15: U26.21@63.05,75.6 64.383,75.6 64.56,75.423 65.64,75.423 65.713,75.35 LNK7.1@72.225,75.35
VDDIO: C19.2 C143.2 C186.2 C187.2 C192.2 C342.2 C380.2 C387.1 C399.1 C400.2 L6.2 LNK11.2 R27.2 R67.2 R260.2 R261.2 U10.F9 U10.F10 U10.F11 U10.F12 U10.L8 U10.L10 U10.M9 U10.N8 U10.N10 U26.29 | length 54.1
  Top Layer w0.09: U10.L10@93.85,71.65 U10.L10@93.874,71.626
  Top Layer w0.2: U26.29@62.6,79.045 62.6,80.298 v2(63.075,80.773) ; C186.2@73.4,71.4 73.585,71.215 LNK11.2@74.6,71.215 ; v3@93.45,71.227 93.45,71.239 93.838,71.626 U10.L10@93.874,71.626
  Top Layer w0.22: v3@91.844,71.227 91.827,71.244 91.833,71.244 92.239,71.65 U10.L8@92.245,71.65 ; v3(91.85,69.525) 91.85,69.65 U10.N8@92.25,70.05 92.325,70.05 v3(92.65,70.375) 92.698,70.423 92.698,70.498 U10.M9@93.05,70.85 93.425,71.225 v3(93.45,71.225) ; U10.F9@93.05,75.65 93.275,75.425 v3(93.45,75.425) 93.625,75.425 U10.F10@93.837,75.638 ; v3(93.45,69.525) 93.45,69.65 U10.N10@93.85,70.05 ; U10.F10@93.825,75.65 U10.F10@93.837,75.638 ; U10.F10@93.85,75.625 U10.F10@93.837,75.638 ; U10.F10@93.85,75.65 U10.F10@93.837,75.638 ; v3(94.25,75.425) 94.475,75.65 U10.F11@94.647,75.65 ; U10.F11@94.647,75.647 U10.F11@94.647,75.65 ; U10.F11@94.65,75.65 U10.F11@94.647,75.65 ; U10.F12@95.445,75.65 U10.F11@94.647,75.65
  Top Layer w0.3: R67.2@71.525,66.375 71.525,66.44 72.01,66.925 73.125,66.925 73.23,67.03 73.339,67.03 73.712,67.402 73.712,69.52 v1(73.752,69.56) ; v1(73.077,69.56) v1@73.125,69.512
  Top Layer w0.64: 73.4,70.525 C186.2@73.4,70.955
  Top Layer w0.9: L6.2@67.85,71.6 68.65,71.6 68.85,71.4 C187.2@69.8,71.4 C19.2@71.6,71.4 C186.2@73.4,71.4
  Signal Layer 2 w0.15: v3(93.45,71.225) 93.45,71.545 93.826,71.921 93.826,75.049 93.825,75.05
  Signal Layer 2 w0.22: v3(93.45,75.425) 93.825,75.05 93.875,75.05 v3(94.25,75.425)
  Signal Layer 2 w0.3: v2(61.284,81.027) 62.799,81.027 63.05,80.776 v2@63.075,80.776 ; v2(63.075,80.773) 63.129,80.773 63.44,81.084 64.543,81.084 64.973,81.513 65.931,81.513 66.455,80.989 66.455,78.601 67.456,77.6 72.999,77.6 73.551,77.048 73.551,75.156 73.951,74.756 73.951,72.573 73.752,72.375 v1(73.752,70.285)
  Bottom Layer w0.15: C143.2@93.05,75.55 93.125,75.475 v3@93.425,75.475
  Bottom Layer w0.22: R27.2@81.95,69.85 81.975,69.875 R27.2@81.975,69.9 v4(81.975,70.45) ; C399.1@91.725,69.15 91.85,69.275 v3(91.85,69.525) ; C387.1@91.725,70.825 91.85,70.95 v3(91.85,71.225) ; v3(92.65,70.375) 92.65,70.125 C192.2@92.775,70 ; C400.2@93.325,69.15 93.45,69.275 v3(93.45,69.525) ; C380.2@93.325,70.85 93.45,70.975 v3(93.45,71.225) ; v3(94.25,75.425) 94.375,75.55 C342.2@94.625,75.55
  Bottom Layer w0.3: R260.2@60.33,81.68 R261.2@61.305,81.68 61.294,81.669 61.294,81.038 v2(61.284,81.027)
  other v1: 73.077,70.285
VDDIO_FB: LNK11.1 U26.17 | length 13.4
  Top Layer w0.15: U26.17@63.17,74 63.7,74 64.303,73.397 v2(64.315,73.397)
  Top Layer w0.2: LNK11.1@74.6,71.665 v2(74.6,73.4)
  Bottom Layer w0.15: v2(64.315,73.397) v2@74.597,73.397
VDDIO_SDCARD: C217.1 C357.2 U10.F14 U26.2 | length 66.6
  Top Layer w0.21: 57.459,71.873 57.8,72.214 U26.2@57.8,72.63
  Top Layer w0.22: U10.F14@97.05,75.65 v3(97.45,76.05)
  Top Layer w0.3: C217.1@56.225,70.38 56.27,70.425 56.559,70.425 56.835,70.701 v2(56.835,70.737)
  Top Layer w0.4: C217.1@56.225,70.32 56.225,70.38 56.225,71.015 56.899,71.69 57.275,71.69 57.459,71.873
  Signal Layer 2 w0.15: 97.035,81.754 97.035,76.465 v3(97.45,76.05)
  Signal Layer 2 w0.5: v4(61.82,85.726) v4(62.398,85.726) 93.063,85.726 97.035,81.754
  Bottom Layer w0.3: v3(97.45,76.05) 97.45,75.675 C357.2@97.55,75.575
  Bottom Layer w0.5: v2(56.835,70.737) 57.009,70.911 57.009,76.91 57.581,77.482 57.581,81.596 57.575,81.601 57.575,82.099 57.581,82.104 57.581,83.542 59.765,85.726 v4(61.82,85.726) v4(62.398,85.726)
VPP_DDR: C91.1 C252.2 C255.2 U17.B1 U17.R9 U26.7 | length 108.2
  Top Layer w0.21: U26.7@59.8,72.63 59.8,71.025 60.215,70.61 60.215,70.253
  Top Layer w0.3: v2(59.74,67.58) C91.1@60.35,67.58 ; 60.215,70.253 60.215,70.118 60.835,69.498 60.835,69.035 60.35,68.55 C91.1@60.35,67.73 ; v2@108.367,78.473 U17.B1@108.927,78.473 ; U17.R9@115.327,68.073 C252.2@116.347,68.073
  Top Layer w0.4: C252.2@116.517,68.218 117.317,68.218
  Top Layer w0.7: v4(106.625,82) 115.637,82 118.594,79.044 118.594,69.47 117.367,68.243 ; v2@116.271,62.342 117.317,63.388 117.317,68.218
  Signal Layer 2 w0.6: v2(59.74,67.58) 59.793,67.58 72.203,55.171
  Signal Layer 2 w0.7: 72.203,55.171 109.095,55.171 v2(116.275,62.35)
  Bottom Layer w0.3: v4(106.625,82) 106.625,81.318 107.623,80.32 107.623,79.852 C255.2@107.675,79.8 ; C255.2@107.788,79.8 107.788,78.98 108.193,78.575 108.211,78.575 108.311,78.475 v2@108.365,78.475
  other v2: 108.365,78.425
VTT_DDR: C40.2 C144.2 C145.2 C146.2 C160.2 C226.2 C239.2 C254.2 C256.2 C257.2 C258.2 C259.2 C261.2 C265.2 C266.2 R252.2 R253.2 R254.2 R255.2 R256.2 R257.2 R258.2 R259.2 R263.2 R264.2 R265.2 R266.2 R268.2 R271.2 R273.2 R275.2 R276.2 R277.2 R278.2 R279.2 R280.2 R281.2 R282.2 R283.2 R284.2 U26.44 | length 89.3
  Top Layer w0.21: 56.275,78 U26.44@56.83,78
  Top Layer w0.25: v1(51.2,78.198) v1@51.202,78.196 ; v1@51.225,77.473 51.202,77.473 51.475,77.2 53.075,77.2 53.32,77.445 53.32,77.635 53.435,77.75 C40.2@53.505,77.75 ; C40.2@53.51,77.635 53.665,77.79 53.94,77.79 54.15,78 56.275,78
  Top Layer w0.5: v1@51.202,77.473 v1@51.202,78.196
  Signal Layer 2 w0.6: v1@51.2,77.5 v1@51.2,78.223
  Signal Layer 2 w0.7: v1@51.15,78.2 49.178,78.2 48.038,77.06 46.623,77.06 45.738,77.946 45.738,85.572 51.638,91.472 94.083,91.472 102.552,83.003 107.122,83.003 v4(107.375,82.75)
  other v1: 51.2,77.473
pads on no net: U10.G17 U10.K17 U10.N17 U10.P17 U17.P9 U17.T7 U24.A1 U24.A2 U24.A7 U24.A8 U24.A9 U24.A10 U24.A11 U24.A12 U24.A13 U24.A14 U24.B1 U24.B7 U24.B8 U24.B9 U24.B10 U24.B11 U24.B12 U24.B13 U24.B14 U24.C1 U24.C3 U24.C5 U24.C7 U24.C8 U24.C9 U24.C10 U24.C11 U24.C12 U24.C13 U24.C14 U24.D1 U24.D2 U24.D3 U24.D4 U24.D12 U24.D13 U24.D14 U24.E1 U24.E2 U24.E3 U24.E5 U24.E8 U24.E9 U24.E10 U24.E12 U24.E13 U24.E14 U24.F1 U24.F2 U24.F3 U24.F10 U24.F12 U24.F13 U24.F14 U24.G1 U24.G2 U24.G3 U24.G10 U24.G12 U24.G13 U24.G14 U24.H1 U24.H2 U24.H3 U24.H12 U24.H13 U24.H14 U24.J1 U24.J2 U24.J3 U24.J12 U24.J13 U24.J14 U24.K1 U24.K2 U24.K3 U24.K6 U24.K7 U24.K10 U24.K12 U24.K13 U24.K14 U24.L1 U24.L2 U24.L3 U24.L12 U24.L13 U24.L14 U24.M1 U24.M2 U24.M3 U24.M7 U24.M8 U24.M9 U24.M10 U24.M11 U24.M12 U24.M13 U24.M14 U24.N1 U24.N3 U24.N6 U24.N7 U24.N8 U24.N9 U24.N10 U24.N11 U24.N12 U24.N13 U24.N14 U24.P1 U24.P2 U24.P7 U24.P8 U24.P9 U24.P10 U24.P11 U24.P12 U24.P13 U24.P14

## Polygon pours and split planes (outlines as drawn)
GND on Bottom Layer "GND_L04" (solid, pour order 155): 0.225,137.075 172,137.075 172,-0.225 0.025,-0.225
VTT_DDR on Bottom Layer "VTT_DDR_L04_P154" (solid, pour order 154): 107.575,80.775 107.025,81.325 107.025,83.075 107.05,83.1 108.3,83.1 108.45,82.95 108.45,81.8 108.625,81.625 111.85,81.625 112.975,80.5 117.7,80.5 118.875,79.325 118.875,75.25 119.9,74.225 119.9,62.275 118.052,62.275 118.099,74.351 117.825,74.625 117.05,74.625 117.05,78.125 116.85,78.325 112.65,78.325 112.325,78.65 112.325,79.875 108.475,79.875
VDD_DDR on Signal Layer 2 "VDD_DDR" (solid, remove dead copper, pour order 144): 49.219,81.75 52.65,81.75 53.225,81.175 53.225,78.95 52.725,78.45 49.211,78.464 48.216,77.468 46.918,77.468 46.246,78.14 46.246,85.378 50.853,89.985 96.09,89.985 106.3,79.775 117.05,79.775 117.05,74.525 118.05,74.525 118.05,62.275 105.572,62.28 98.912,68.94 98.476,68.94 97.25,70.174 97.25,81.325 94.48,84.095 49.539,84.095 49.219,83.775
GND on Signal Layer 2 "GND_L03" (solid, remove dead copper, pour order 152): -0.042,136.898 172,136.898 172,-0.102 -0.042,-0.102
1V8 on Signal Layer 2 "1V8" (solid, pour order 151): 60.675,96.6 60.675,93.472 101.693,93.472 101.748,83.8 116.35,83.8 117.725,85.175 117.725,96.6
VDDIO on Signal Layer 2 "VDDIO_L03" (solid, remove dead copper, pour order 145): 93.617,71.95 93.613,71.945 93.613,69.59 91.403,69.59 89.378,67.564 74.378,67.564 72.553,69.389 72.553,71.646 73.744,72.838 90.259,72.838 91.146,71.95
VDDCPU on Signal Layer 2 "VDDCPU" (solid, remove dead copper, pour order 143): 94.074,72.5 94.074,74.752 93.212,75.614 93.212,76.951 91.618,78.545 81.766,78.735 66.455,78.545 66.455,80.62 66.505,80.67 66.175,81 60.143,81 60.055,80.912 59.116,81.85 49.319,81.85 49.219,81.75 49.219,83.775 50.843,85.4 59.717,85.4 60.603,84.513 60.603,84.5 93.85,84.5 96.931,81.419 96.931,72.5
5V_STLK on Signal Layer 2 "5V_STLK_L03" (solid, pour order 150): 43.375,82.635 68.35,82.635 68.35,66.229 43.411,66.229
3V3 on Signal Layer 2 "3V3_L03" (solid, remove dead copper, pour order 146): 58,61.394 57.939,61.394 37.983,61.394 35.711,61.394 35.711,67.822 35.711,84.011 44.436,84.011 44.436,73.55 45.447,72.539 58,72.539
VDDCORE on Signal Layer 2 "VDDCORE" (solid, remove dead copper, pour order 142): 85.2,78.6 85.925,79.325 91.1,79.325 91.55,78.875 91.542,78.592 93.08,77.054 93.08,75.225 93.657,74.608 93.657,72.016 93.508,71.868 90.93,71.868 89.779,73.018 73.707,73.018 73.707,78.6
VDDGPU on Signal Layer 2 "VDDGPU" (solid, remove dead copper, pour order 127): 97.148,69.67 97.148,72.308 94.868,72.308 93.988,72.308 93.666,71.986 93.666,70.788 93.666,69.512 91.192,69.512 89.374,67.715 74.374,67.715 72.549,69.54 72.549,71.782 73.63,72.863 73.63,77.29 68.13,77.29 66.599,75.759 66.599,73.523 68.4,71.766 68.4,66.459 74.813,60.175 93.875,60.175 98.541,64.841 98.541,68.277 97.306,69.512
GND on Top Layer "GND_L01" (solid, pour order 153): 0.178,137.102 0.303,136.977 172,136.977 172,-0.323 0.103,-0.323
VDDCORE on Top Layer "I_SENS_VDDCORE_P" (solid, pour order 134): 72.507,84.74 75.389,81.858 75.389,75.631 75.394,75.626 73.94,75.626 73.395,76.171 73.395,80.872 73.022,81.245 71.375,81.245 67.015,81.245 67.005,84.74
3V3 on Top Layer "3V3" (solid, pour order 137): 44.387,68.548 44.562,68.373 50.91,68.373 52.212,69.675 52.212,70.523 44.588,70.523 44.387,70.323
5V_STLK on Top Layer "5V_STK" (solid, pour order 111): 54.01,75.62 54.667,75.62 54.85,75.803 54.85,75.463 54.367,74.98 54.01,74.98
VDDCPU on Top Layer "I_SENS_VDDCPU_P" (solid, pour order 133): 49.312,83.845 49.312,81.998 49.835,81.475 54.25,81.475 54.245,81.48 54.245,83.845
VDDGPU on Top Layer "I_SENS_VDDGPU_P" (solid, pour order 135): 73.103,75.6 73.245,75.742 73.245,78.72 68.525,78.72 68.525,75.6
VDDIO on Top Layer "VDDIO" (solid, pour order 136): 62.495,78.77 62.495,80.568 63.03,81.103 63.212,81.103 63.65,80.664 63.65,80.123 62.95,79.423 62.95,78.77
NetL6_1 on Top Layer "NetL6_1" (solid, pour order 138): 64.875,73.863 65.338,73.4 66.6,73.4 66.6,71.1 66.598,71.098 65.301,71.098 65.301,72.722 64.875,73.148
GND on Signal Layer 1 "GND_L02" (solid, remove dead copper, pour order 99): -1,138 172,138 172,-1 -1,-1

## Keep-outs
Keep-Out Layer:
  lines w0.1: 133.661,133.38 142.561,133.38 142.561,135.53 133.661,135.53 133.661,133.38

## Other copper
Top Layer:
  rectangle net VDD_DDR: 47.155,73.8 50.125,75.6
  text "1" at 134.025,133.812 h2
Signal Layer 1:
  text "2" at 135.312,133.812 h2
Signal Layer 2:
  text "5" at 140.661,133.834 h2
Bottom Layer:
  text "6" at 142.159,133.823 h2

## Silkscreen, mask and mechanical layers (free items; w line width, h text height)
Top Overlay:
  text "J" at 47.238,116.435 h15
  text "VBAT" at 63.016,59.792 h1.2
Top Solder:
  region: 133.736,135.455 133.736,133.455 142.486,133.455 142.486,135.455
Bottom Solder:
  region: 133.736,135.455 133.736,133.455 142.486,133.455 142.486,135.455
M1-Board Shape:
  lines w0.1: 1,137 ccw(c1,136) 0,136 0,95 0,1 ccw(c1,1) 1,0 171,0 ccw(c171,1) 172,1 172,136 ccw(c171,136) 171,137 ; 1,137 1,137 ; 1,137 171,137 ; 171,137 171,137
M2-Board Dimensions:
  lines w0.1: 1,137 ccw(c1,136) 0,136 0,1 ccw(c1,1) 1,0 171,0 ccw(c171,1) 172,1 172,136 ccw(c171,136) 171,137 ; 1,137 1,137 ; 1,137 171,137 ; 171,137 171,137
Drill Drawing:
  drawing of 183 lines, arcs and shapes, not listed
  text "PCB SPECIFICATIONS :" at 3.455,183.85 h3
  text "MINIMUN PARAMETERS" at 155.325,183.145 h3
  text "PCB : TYPE 3" at 194.663,183.121 h3
  text "A.   MATERIAL :" at 3.455,179.85 h3
  text "FR-4" at 41.955,179.85 h3
  text "TG-170" at 58.455,179.85 h3
  text "X  TG-150" at 76.705,179.85 h3
  text "TG-140" at 92.705,179.85 h3
  text "DEFAULT" at 155.325,177.645 h3
  text "ASPECT-RATIO, AXE Z :" at 194.663,177.621 h3
  text "B.   MATERIAL FAMILY :" at 3.455,176.85 h3
  text "N/A" at 41.955,176.85 h3
  text "C.   SOLDERMASK COLOR :" at 3.455,173.85 h3
  text "GREEN" at 41.955,173.85 h3
  text "X  BLUE" at 58.455,173.85 h3
  text "RED" at 76.705,173.85 h3
  text "BLACK" at 92.705,173.85 h3
  text "TRACKS : 0.100mm           / GAPS : 0.100mm" at 155.325,171.895 h3
  text "6 :1  to  8 :1 / LEVEL \"B\"" at 194.682,170.874 h3
  text "D.   SILKSCREEN COLOR :" at 3.455,170.85 h3
  text "X  WHITE" at 41.955,170.85 h3
  text "YELLOW" at 58.455,170.85 h3
  text "BLACK" at 76.705,170.85 h3
  text "E.   SURFACE FINISH :" at 3.455,167.85 h3
  text "X  ENIG" at 41.955,167.85 h3
  text "IMMERSION SILVER" at 58.455,167.85 h3
  text "IMMERSION TIN" at 92.705,167.85 h3
  text "BGA :" at 155.3,167.07 h3
  text "Layer" at 244.479,166.45 h2
  text "Name" at 252.843,166.45 h2
  text "Material" at 269.012,166.45 h2
  text "Thickness" at 283.545,166.45 h2
  text "Constant" at 295.481,166.45 h2
  text "HASL" at 41.955,164.85 h3
  text "HASL (PB-FREE)" at 58.455,164.85 h3
  text "GOLDEN FINGER" at 92.705,164.85 h3
  text "Top Overlay" at 252.843,162.45 h2
  text "F.   IMPEDANCE CONTROL :" at 3.455,161.85 h3
  text "NO" at 41.955,161.85 h3
  text "X  YES" at 58.455,161.85 h3
  text "TRACKS : 0.090mm           / GAPS : 0.090mm" at 155.3,161.32 h3
  text "G.   THROUGH VIA :" at 3.455,158.85 h3
  text "PLUG THE VIAS WHICH ARE COVERED WITH SOLDERMASK ONE OR TWO SIDE." at 41.955,158.85 h3
  text "Top Solder" at 252.843,158.45 h2
  text "Solder Resist" at 269.012,158.45 h2
  text "0.025mm" at 283.545,158.45 h2
  text "3.5" at 295.481,158.45 h2
  text "PLUG MATERIAL :" at 41.955,155.85 h3
  text "X  SOLDERMASK" at 67.455,155.85 h3
  text "NON-CONDUCTIVE EPOXY." at 92.705,155.85 h3
  text "1" at 244.479,154.45 h2
  text "Top Layer" at 252.843,154.45 h2
  text "0.037mm" at 283.545,154.45 h2
  text "H.   STACK-UP :" at 3.455,152.85 h3
  text "SEE LAYER STACK-UP SEQUENCE FOR OVERALL THICKNESS." at 41.955,152.85 h3
  text "Dielectric 1" at 252.843,150.45 h2
  text "0.070mm" at 283.545,150.45 h2
  text "3.8" at 295.481,150.45 h2
  text "2" at 244.478,146.45 h2
  text "Signal Layer 1" at 252.843,146.45 h2
  text "0.035mm" at 283.545,146.45 h2
  text "Dielectric 2" at 252.843,142.45 h2
  text "1.330mm" at 283.545,142.45 h2
  text "4.3" at 295.481,142.45 h2
  text "3" at 244.479,138.45 h2
  text "Signal Layer 2" at 252.843,138.45 h2
  text "0.035mm" at 283.545,138.45 h2
  text "Dielectric 3" at 252.843,134.45 h2
  text "0.070mm" at 283.545,134.45 h2
  text "3.8" at 295.481,134.45 h2
  text "4" at 244.479,130.45 h2
  text "Bottom Layer" at 252.843,130.45 h2
  text "0.037mm" at 283.545,130.45 h2
  text "Bottom Solder" at 252.843,126.45 h2
  text "Solder Resist" at 269.012,126.45 h2
  text "0.025mm" at 283.545,126.45 h2
  text "3.5" at 295.481,126.45 h2
  text "Bottom Overlay" at 252.843,122.45 h2
  text "Symbol" at 183.641,16.141 h2.4
  text "Count" at 193.03,16.141 h2.4
  text "Hole Size" at 202.766,16.141 h2.4
  text "Plated" at 221,16.141 h2.4
  text "Hole Type" at 229.244,16.141 h2.4
  text "Drill Layer Pair" at 241.243,16.141 h2.4
  text "Via/Pad" at 263.972,16.141 h2.4
  text "Pad Shape" at 273.804,16.141 h2.4
  text "Hole Length" at 286.649,16.141 h2.4
  text "506" at 193.03,12.004 h2
  text "0.200mm (7.87mil)" at 202.766,12.004 h2
  text "PTH" at 221,12.004 h2
  text "Round" at 229.244,12.004 h2
  text "Top Layer - Bottom Layer" at 241.243,12.004 h2
  text "Via" at 263.972,12.004 h2
  text "Rounded" at 273.804,12.004 h2
  text "-" at 286.649,12.004 h2
  text "D" at 182.854,11.75 h1.84
  text "344" at 193.03,7.867 h2
  text "0.350mm (13.78mil)" at 202.766,7.867 h2
  text "PTH" at 221,7.867 h2
  text "Round" at 229.244,7.867 h2
  text "Top Layer - Bottom Layer" at 241.243,7.867 h2
  text "Via" at 263.972,7.867 h2
  text "Rounded" at 273.804,7.867 h2
  text "-" at 286.649,7.867 h2
  text "F" at 182.854,7.613 h1.84
  text "2" at 193.03,3.729 h2
  text "0.500mm (19.69mil)" at 202.766,3.729 h2
  text "PTH" at 221,3.729 h2
  text "Round" at 229.244,3.729 h2
  text "Top Layer - Bottom Layer" at 241.243,3.729 h2
  text "Pad" at 263.972,3.729 h2
  text "Rounded" at 273.804,3.729 h2
  text "-" at 286.649,3.729 h2
  text "852 Total" at 193.03,-0.408 h2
